VERSION 5.7 ;
  NOWIREEXTENSIONATPIN ON ;
  DIVIDERCHAR "/" ;
  BUSBITCHARS "[]" ;
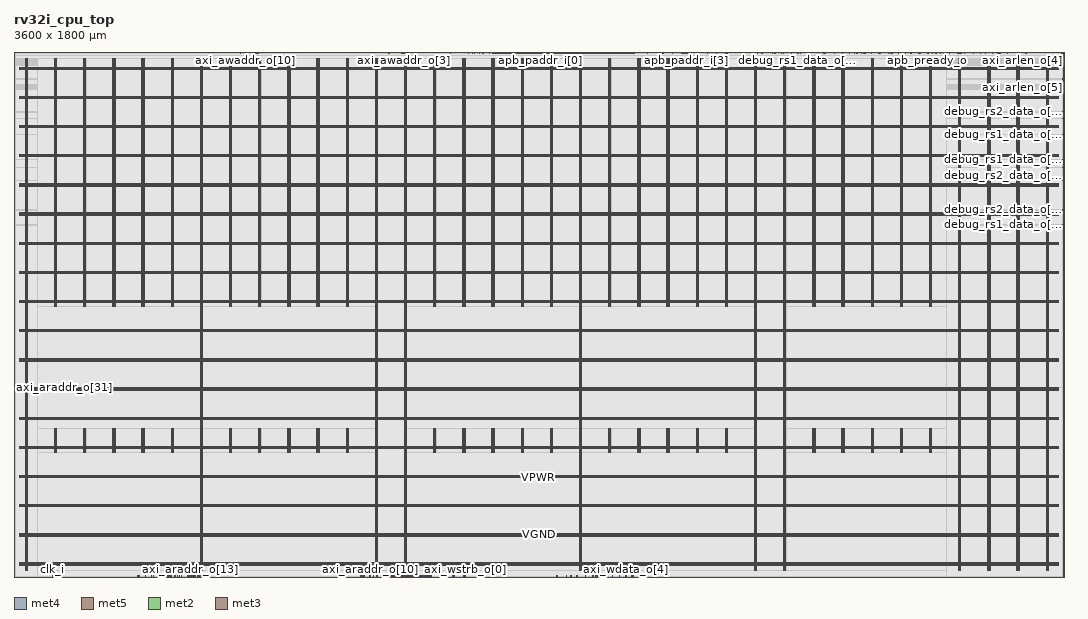
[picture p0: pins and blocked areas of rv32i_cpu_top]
MACRO rv32i_cpu_top
  CLASS BLOCK ;
  FOREIGN rv32i_cpu_top ;
  ORIGIN 0.000 0.000 ;
  SIZE 3600.000 BY 1800.000 ;
  PIN VGND
    DIRECTION INOUT ;
    USE GROUND ;
    PORT
      LAYER met4 ;
        RECT 43.490 21.520 46.590 1779.120 ;
    END
    PORT
      LAYER met4 ;
        RECT 143.490 427.280 146.590 510.220 ;
    END
    PORT
      LAYER met4 ;
        RECT 143.490 927.280 146.590 1779.120 ;
    END
    PORT
      LAYER met4 ;
        RECT 243.490 427.280 246.590 509.300 ;
    END
    PORT
      LAYER met4 ;
        RECT 243.490 927.280 246.590 1779.120 ;
    END
    PORT
      LAYER met4 ;
        RECT 343.490 427.280 346.590 509.300 ;
    END
    PORT
      LAYER met4 ;
        RECT 343.490 927.280 346.590 1779.120 ;
    END
    PORT
      LAYER met4 ;
        RECT 443.490 427.280 446.590 510.220 ;
    END
    PORT
      LAYER met4 ;
        RECT 443.490 927.280 446.590 1779.120 ;
    END
    PORT
      LAYER met4 ;
        RECT 543.490 427.280 546.590 510.220 ;
    END
    PORT
      LAYER met4 ;
        RECT 543.490 927.280 546.590 1779.120 ;
    END
    PORT
      LAYER met4 ;
        RECT 643.490 21.520 646.590 1779.120 ;
    END
    PORT
      LAYER met4 ;
        RECT 743.490 427.280 746.590 510.220 ;
    END
    PORT
      LAYER met4 ;
        RECT 743.490 927.280 746.590 1779.120 ;
    END
    PORT
      LAYER met4 ;
        RECT 843.490 428.200 846.590 509.300 ;
    END
    PORT
      LAYER met4 ;
        RECT 843.490 928.200 846.590 1779.120 ;
    END
    PORT
      LAYER met4 ;
        RECT 943.490 428.200 946.590 509.300 ;
    END
    PORT
      LAYER met4 ;
        RECT 943.490 928.200 946.590 1779.120 ;
    END
    PORT
      LAYER met4 ;
        RECT 1043.490 427.280 1046.590 510.220 ;
    END
    PORT
      LAYER met4 ;
        RECT 1043.490 927.280 1046.590 1779.120 ;
    END
    PORT
      LAYER met4 ;
        RECT 1143.490 427.280 1146.590 510.220 ;
    END
    PORT
      LAYER met4 ;
        RECT 1143.490 927.280 1146.590 1779.120 ;
    END
    PORT
      LAYER met4 ;
        RECT 1243.490 21.520 1246.590 1779.120 ;
    END
    PORT
      LAYER met4 ;
        RECT 1343.490 21.520 1346.590 1779.120 ;
    END
    PORT
      LAYER met4 ;
        RECT 1443.490 427.280 1446.590 509.300 ;
    END
    PORT
      LAYER met4 ;
        RECT 1443.490 927.280 1446.590 1779.120 ;
    END
    PORT
      LAYER met4 ;
        RECT 1543.490 428.200 1546.590 509.300 ;
    END
    PORT
      LAYER met4 ;
        RECT 1543.490 928.200 1546.590 1779.120 ;
    END
    PORT
      LAYER met4 ;
        RECT 1643.490 428.200 1646.590 509.300 ;
    END
    PORT
      LAYER met4 ;
        RECT 1643.490 928.200 1646.590 1779.120 ;
    END
    PORT
      LAYER met4 ;
        RECT 1743.490 427.280 1746.590 510.220 ;
    END
    PORT
      LAYER met4 ;
        RECT 1743.490 927.280 1746.590 1779.120 ;
    END
    PORT
      LAYER met4 ;
        RECT 1843.490 427.280 1846.590 510.220 ;
    END
    PORT
      LAYER met4 ;
        RECT 1843.490 927.280 1846.590 1779.120 ;
    END
    PORT
      LAYER met4 ;
        RECT 1943.490 21.520 1946.590 1779.120 ;
    END
    PORT
      LAYER met4 ;
        RECT 2043.490 427.280 2046.590 510.220 ;
    END
    PORT
      LAYER met4 ;
        RECT 2043.490 927.280 2046.590 1779.120 ;
    END
    PORT
      LAYER met4 ;
        RECT 2143.490 427.280 2146.590 509.300 ;
    END
    PORT
      LAYER met4 ;
        RECT 2143.490 927.280 2146.590 1779.120 ;
    END
    PORT
      LAYER met4 ;
        RECT 2243.490 428.200 2246.590 509.300 ;
    END
    PORT
      LAYER met4 ;
        RECT 2243.490 928.200 2246.590 1779.120 ;
    END
    PORT
      LAYER met4 ;
        RECT 2343.490 428.200 2346.590 510.220 ;
    END
    PORT
      LAYER met4 ;
        RECT 2343.490 928.200 2346.590 1779.120 ;
    END
    PORT
      LAYER met4 ;
        RECT 2443.490 427.280 2446.590 510.220 ;
    END
    PORT
      LAYER met4 ;
        RECT 2443.490 927.280 2446.590 1779.120 ;
    END
    PORT
      LAYER met4 ;
        RECT 2543.490 21.520 2546.590 1779.120 ;
    END
    PORT
      LAYER met4 ;
        RECT 2643.490 21.520 2646.590 1779.120 ;
    END
    PORT
      LAYER met4 ;
        RECT 2743.490 427.280 2746.590 510.220 ;
    END
    PORT
      LAYER met4 ;
        RECT 2743.490 927.280 2746.590 1779.120 ;
    END
    PORT
      LAYER met4 ;
        RECT 2843.490 427.280 2846.590 509.300 ;
    END
    PORT
      LAYER met4 ;
        RECT 2843.490 927.280 2846.590 1779.120 ;
    END
    PORT
      LAYER met4 ;
        RECT 2943.490 428.200 2946.590 509.300 ;
    END
    PORT
      LAYER met4 ;
        RECT 2943.490 928.200 2946.590 1779.120 ;
    END
    PORT
      LAYER met4 ;
        RECT 3043.490 428.200 3046.590 509.300 ;
    END
    PORT
      LAYER met4 ;
        RECT 3043.490 928.200 3046.590 1779.120 ;
    END
    PORT
      LAYER met4 ;
        RECT 3143.490 427.280 3146.590 510.220 ;
    END
    PORT
      LAYER met4 ;
        RECT 3143.490 927.280 3146.590 1779.120 ;
    END
    PORT
      LAYER met4 ;
        RECT 3243.490 21.520 3246.590 1779.120 ;
    END
    PORT
      LAYER met4 ;
        RECT 3343.490 21.520 3346.590 1779.120 ;
    END
    PORT
      LAYER met4 ;
        RECT 3443.490 21.520 3446.590 1779.120 ;
    END
    PORT
      LAYER met4 ;
        RECT 3543.490 21.520 3546.590 1779.120 ;
    END
    PORT
      LAYER met5 ;
        RECT 20.000 45.010 3579.960 48.110 ;
    END
    PORT
      LAYER met5 ;
        RECT 20.000 145.010 3579.960 148.110 ;
    END
    PORT
      LAYER met5 ;
        RECT 20.000 245.010 3579.960 248.110 ;
    END
    PORT
      LAYER met5 ;
        RECT 20.000 345.010 3579.960 348.110 ;
    END
    PORT
      LAYER met5 ;
        RECT 20.000 445.010 3579.960 448.110 ;
    END
    PORT
      LAYER met5 ;
        RECT 20.000 545.010 3579.960 548.110 ;
    END
    PORT
      LAYER met5 ;
        RECT 20.000 645.010 3579.960 648.110 ;
    END
    PORT
      LAYER met5 ;
        RECT 20.000 745.010 3579.960 748.110 ;
    END
    PORT
      LAYER met5 ;
        RECT 20.000 845.010 3579.960 848.110 ;
    END
    PORT
      LAYER met5 ;
        RECT 20.000 945.010 3579.960 948.110 ;
    END
    PORT
      LAYER met5 ;
        RECT 20.000 1045.010 3579.960 1048.110 ;
    END
    PORT
      LAYER met5 ;
        RECT 20.000 1145.010 3579.960 1148.110 ;
    END
    PORT
      LAYER met5 ;
        RECT 20.000 1245.010 3579.960 1248.110 ;
    END
    PORT
      LAYER met5 ;
        RECT 20.000 1345.010 3579.960 1348.110 ;
    END
    PORT
      LAYER met5 ;
        RECT 20.000 1445.010 3579.960 1448.110 ;
    END
    PORT
      LAYER met5 ;
        RECT 20.000 1545.010 3579.960 1548.110 ;
    END
    PORT
      LAYER met5 ;
        RECT 20.000 1645.010 3579.960 1648.110 ;
    END
    PORT
      LAYER met5 ;
        RECT 20.000 1745.010 3579.960 1748.110 ;
    END
  END VGND
  PIN VPWR
    DIRECTION INOUT ;
    USE POWER ;
    PORT
      LAYER met4 ;
        RECT 38.690 21.520 41.790 1779.120 ;
    END
    PORT
      LAYER met4 ;
        RECT 138.690 427.280 141.790 510.220 ;
    END
    PORT
      LAYER met4 ;
        RECT 138.690 927.280 141.790 1779.120 ;
    END
    PORT
      LAYER met4 ;
        RECT 238.690 428.200 241.790 509.300 ;
    END
    PORT
      LAYER met4 ;
        RECT 238.690 928.200 241.790 1779.120 ;
    END
    PORT
      LAYER met4 ;
        RECT 338.690 428.200 341.790 509.300 ;
    END
    PORT
      LAYER met4 ;
        RECT 338.690 928.200 341.790 1779.120 ;
    END
    PORT
      LAYER met4 ;
        RECT 438.690 427.280 441.790 510.220 ;
    END
    PORT
      LAYER met4 ;
        RECT 438.690 927.280 441.790 1779.120 ;
    END
    PORT
      LAYER met4 ;
        RECT 538.690 427.280 541.790 510.220 ;
    END
    PORT
      LAYER met4 ;
        RECT 538.690 927.280 541.790 1779.120 ;
    END
    PORT
      LAYER met4 ;
        RECT 638.690 21.520 641.790 1779.120 ;
    END
    PORT
      LAYER met4 ;
        RECT 738.690 427.280 741.790 510.220 ;
    END
    PORT
      LAYER met4 ;
        RECT 738.690 927.280 741.790 1779.120 ;
    END
    PORT
      LAYER met4 ;
        RECT 838.690 428.200 841.790 509.300 ;
    END
    PORT
      LAYER met4 ;
        RECT 838.690 928.200 841.790 1779.120 ;
    END
    PORT
      LAYER met4 ;
        RECT 938.690 428.200 941.790 509.300 ;
    END
    PORT
      LAYER met4 ;
        RECT 938.690 928.200 941.790 1779.120 ;
    END
    PORT
      LAYER met4 ;
        RECT 1038.690 427.280 1041.790 510.220 ;
    END
    PORT
      LAYER met4 ;
        RECT 1038.690 927.280 1041.790 1779.120 ;
    END
    PORT
      LAYER met4 ;
        RECT 1138.690 427.280 1141.790 510.220 ;
    END
    PORT
      LAYER met4 ;
        RECT 1138.690 927.280 1141.790 1779.120 ;
    END
    PORT
      LAYER met4 ;
        RECT 1238.690 21.520 1241.790 1779.120 ;
    END
    PORT
      LAYER met4 ;
        RECT 1338.690 21.520 1341.790 1779.120 ;
    END
    PORT
      LAYER met4 ;
        RECT 1438.690 427.280 1441.790 510.220 ;
    END
    PORT
      LAYER met4 ;
        RECT 1438.690 927.280 1441.790 1779.120 ;
    END
    PORT
      LAYER met4 ;
        RECT 1538.690 428.200 1541.790 509.300 ;
    END
    PORT
      LAYER met4 ;
        RECT 1538.690 928.200 1541.790 1779.120 ;
    END
    PORT
      LAYER met4 ;
        RECT 1638.690 428.200 1641.790 509.300 ;
    END
    PORT
      LAYER met4 ;
        RECT 1638.690 928.200 1641.790 1779.120 ;
    END
    PORT
      LAYER met4 ;
        RECT 1738.690 427.280 1741.790 510.220 ;
    END
    PORT
      LAYER met4 ;
        RECT 1738.690 927.280 1741.790 1779.120 ;
    END
    PORT
      LAYER met4 ;
        RECT 1838.690 427.280 1841.790 510.220 ;
    END
    PORT
      LAYER met4 ;
        RECT 1838.690 927.280 1841.790 1779.120 ;
    END
    PORT
      LAYER met4 ;
        RECT 1938.690 21.520 1941.790 1779.120 ;
    END
    PORT
      LAYER met4 ;
        RECT 2038.690 427.280 2041.790 510.220 ;
    END
    PORT
      LAYER met4 ;
        RECT 2038.690 927.280 2041.790 1779.120 ;
    END
    PORT
      LAYER met4 ;
        RECT 2138.690 427.280 2141.790 509.300 ;
    END
    PORT
      LAYER met4 ;
        RECT 2138.690 927.280 2141.790 1779.120 ;
    END
    PORT
      LAYER met4 ;
        RECT 2238.690 427.280 2241.790 509.300 ;
    END
    PORT
      LAYER met4 ;
        RECT 2238.690 927.280 2241.790 1779.120 ;
    END
    PORT
      LAYER met4 ;
        RECT 2338.690 427.280 2341.790 509.300 ;
    END
    PORT
      LAYER met4 ;
        RECT 2338.690 927.280 2341.790 1779.120 ;
    END
    PORT
      LAYER met4 ;
        RECT 2438.690 427.280 2441.790 510.220 ;
    END
    PORT
      LAYER met4 ;
        RECT 2438.690 927.280 2441.790 1779.120 ;
    END
    PORT
      LAYER met4 ;
        RECT 2538.690 21.520 2541.790 1779.120 ;
    END
    PORT
      LAYER met4 ;
        RECT 2638.690 21.520 2641.790 1779.120 ;
    END
    PORT
      LAYER met4 ;
        RECT 2738.690 427.280 2741.790 510.220 ;
    END
    PORT
      LAYER met4 ;
        RECT 2738.690 927.280 2741.790 1779.120 ;
    END
    PORT
      LAYER met4 ;
        RECT 2838.690 427.280 2841.790 510.220 ;
    END
    PORT
      LAYER met4 ;
        RECT 2838.690 927.280 2841.790 1779.120 ;
    END
    PORT
      LAYER met4 ;
        RECT 2938.690 428.200 2941.790 509.300 ;
    END
    PORT
      LAYER met4 ;
        RECT 2938.690 928.200 2941.790 1779.120 ;
    END
    PORT
      LAYER met4 ;
        RECT 3038.690 428.200 3041.790 509.300 ;
    END
    PORT
      LAYER met4 ;
        RECT 3038.690 928.200 3041.790 1779.120 ;
    END
    PORT
      LAYER met4 ;
        RECT 3138.690 427.280 3141.790 510.220 ;
    END
    PORT
      LAYER met4 ;
        RECT 3138.690 927.280 3141.790 1779.120 ;
    END
    PORT
      LAYER met4 ;
        RECT 3238.690 21.520 3241.790 1779.120 ;
    END
    PORT
      LAYER met4 ;
        RECT 3338.690 21.520 3341.790 1779.120 ;
    END
    PORT
      LAYER met4 ;
        RECT 3438.690 21.520 3441.790 1779.120 ;
    END
    PORT
      LAYER met4 ;
        RECT 3538.690 21.520 3541.790 1779.120 ;
    END
    PORT
      LAYER met5 ;
        RECT 20.000 40.210 3579.960 43.310 ;
    END
    PORT
      LAYER met5 ;
        RECT 20.000 140.210 3579.960 143.310 ;
    END
    PORT
      LAYER met5 ;
        RECT 20.000 240.210 3579.960 243.310 ;
    END
    PORT
      LAYER met5 ;
        RECT 20.000 340.210 3579.960 343.310 ;
    END
    PORT
      LAYER met5 ;
        RECT 20.000 440.210 3579.960 443.310 ;
    END
    PORT
      LAYER met5 ;
        RECT 20.000 540.210 3579.960 543.310 ;
    END
    PORT
      LAYER met5 ;
        RECT 20.000 640.210 3579.960 643.310 ;
    END
    PORT
      LAYER met5 ;
        RECT 20.000 740.210 3579.960 743.310 ;
    END
    PORT
      LAYER met5 ;
        RECT 20.000 840.210 3579.960 843.310 ;
    END
    PORT
      LAYER met5 ;
        RECT 20.000 940.210 3579.960 943.310 ;
    END
    PORT
      LAYER met5 ;
        RECT 20.000 1040.210 3579.960 1043.310 ;
    END
    PORT
      LAYER met5 ;
        RECT 20.000 1140.210 3579.960 1143.310 ;
    END
    PORT
      LAYER met5 ;
        RECT 20.000 1240.210 3579.960 1243.310 ;
    END
    PORT
      LAYER met5 ;
        RECT 20.000 1340.210 3579.960 1343.310 ;
    END
    PORT
      LAYER met5 ;
        RECT 20.000 1440.210 3579.960 1443.310 ;
    END
    PORT
      LAYER met5 ;
        RECT 20.000 1540.210 3579.960 1543.310 ;
    END
    PORT
      LAYER met5 ;
        RECT 20.000 1640.210 3579.960 1643.310 ;
    END
    PORT
      LAYER met5 ;
        RECT 20.000 1740.210 3579.960 1743.310 ;
    END
  END VPWR
  PIN apb_paddr_i[0]
    DIRECTION INPUT ;
    USE SIGNAL ;
    ANTENNAGATEAREA 0.647700 ;
    ANTENNADIFFAREA 0.434700 ;
    PORT
      LAYER met2 ;
        RECT 1806.510 1796.000 1806.790 1800.000 ;
    END
  END apb_paddr_i[0]
  PIN apb_paddr_i[10]
    DIRECTION INPUT ;
    USE SIGNAL ;
    ANTENNAGATEAREA 2.276700 ;
    ANTENNADIFFAREA 0.434700 ;
    PORT
      LAYER met2 ;
        RECT 1777.530 1796.000 1777.810 1800.000 ;
    END
  END apb_paddr_i[10]
  PIN apb_paddr_i[11]
    DIRECTION INPUT ;
    USE SIGNAL ;
    ANTENNAGATEAREA 0.929700 ;
    ANTENNADIFFAREA 0.434700 ;
    PORT
      LAYER met2 ;
        RECT 1774.310 1796.000 1774.590 1800.000 ;
    END
  END apb_paddr_i[11]
  PIN apb_paddr_i[1]
    DIRECTION INPUT ;
    USE SIGNAL ;
    ANTENNAGATEAREA 0.647700 ;
    ANTENNADIFFAREA 0.434700 ;
    PORT
      LAYER met2 ;
        RECT 1793.630 1796.000 1793.910 1800.000 ;
    END
  END apb_paddr_i[1]
  PIN apb_paddr_i[2]
    DIRECTION INPUT ;
    USE SIGNAL ;
    ANTENNAGATEAREA 0.647700 ;
    ANTENNADIFFAREA 0.434700 ;
    PORT
      LAYER met2 ;
        RECT 2308.830 1796.000 2309.110 1800.000 ;
    END
  END apb_paddr_i[2]
  PIN apb_paddr_i[3]
    DIRECTION INPUT ;
    USE SIGNAL ;
    ANTENNAGATEAREA 0.631200 ;
    ANTENNADIFFAREA 0.434700 ;
    PORT
      LAYER met2 ;
        RECT 2305.610 1796.000 2305.890 1800.000 ;
    END
  END apb_paddr_i[3]
  PIN apb_paddr_i[4]
    DIRECTION INPUT ;
    USE SIGNAL ;
    ANTENNAGATEAREA 0.929700 ;
    ANTENNADIFFAREA 0.434700 ;
    PORT
      LAYER met2 ;
        RECT 2302.390 1796.000 2302.670 1800.000 ;
    END
  END apb_paddr_i[4]
  PIN apb_paddr_i[5]
    DIRECTION INPUT ;
    USE SIGNAL ;
    ANTENNAGATEAREA 0.860700 ;
    ANTENNADIFFAREA 0.434700 ;
    PORT
      LAYER met2 ;
        RECT 2295.950 1796.000 2296.230 1800.000 ;
    END
  END apb_paddr_i[5]
  PIN apb_paddr_i[6]
    DIRECTION INPUT ;
    USE SIGNAL ;
    ANTENNAGATEAREA 0.860700 ;
    ANTENNADIFFAREA 0.434700 ;
    PORT
      LAYER met2 ;
        RECT 2299.170 1796.000 2299.450 1800.000 ;
    END
  END apb_paddr_i[6]
  PIN apb_paddr_i[7]
    DIRECTION INPUT ;
    USE SIGNAL ;
    ANTENNAGATEAREA 0.682200 ;
    ANTENNADIFFAREA 0.434700 ;
    PORT
      LAYER met2 ;
        RECT 2292.730 1796.000 2293.010 1800.000 ;
    END
  END apb_paddr_i[7]
  PIN apb_paddr_i[8]
    DIRECTION INPUT ;
    USE SIGNAL ;
    ANTENNAGATEAREA 1.177200 ;
    ANTENNADIFFAREA 0.434700 ;
    PORT
      LAYER met2 ;
        RECT 1780.750 1796.000 1781.030 1800.000 ;
    END
  END apb_paddr_i[8]
  PIN apb_paddr_i[9]
    DIRECTION INPUT ;
    USE SIGNAL ;
    ANTENNAGATEAREA 0.647700 ;
    ANTENNADIFFAREA 0.434700 ;
    PORT
      LAYER met2 ;
        RECT 1687.370 1796.000 1687.650 1800.000 ;
    END
  END apb_paddr_i[9]
  PIN apb_penable_i
    DIRECTION INPUT ;
    USE SIGNAL ;
    ANTENNAGATEAREA 0.560700 ;
    ANTENNADIFFAREA 0.434700 ;
    PORT
      LAYER met2 ;
        RECT 2128.510 1796.000 2128.790 1800.000 ;
    END
  END apb_penable_i
  PIN apb_prdata_o[0]
    DIRECTION OUTPUT ;
    USE SIGNAL ;
    ANTENNADIFFAREA 1.782000 ;
    PORT
      LAYER met2 ;
        RECT 1832.270 1796.000 1832.550 1800.000 ;
    END
  END apb_prdata_o[0]
  PIN apb_prdata_o[10]
    DIRECTION OUTPUT ;
    USE SIGNAL ;
    ANTENNADIFFAREA 1.336500 ;
    PORT
      LAYER met2 ;
        RECT 1809.730 1796.000 1810.010 1800.000 ;
    END
  END apb_prdata_o[10]
  PIN apb_prdata_o[11]
    DIRECTION OUTPUT ;
    USE SIGNAL ;
    ANTENNADIFFAREA 0.891000 ;
    PORT
      LAYER met2 ;
        RECT 1800.070 1796.000 1800.350 1800.000 ;
    END
  END apb_prdata_o[11]
  PIN apb_prdata_o[12]
    DIRECTION OUTPUT ;
    USE SIGNAL ;
    ANTENNADIFFAREA 1.782000 ;
    PORT
      LAYER met2 ;
        RECT 2080.210 1796.000 2080.490 1800.000 ;
    END
  END apb_prdata_o[12]
  PIN apb_prdata_o[13]
    DIRECTION OUTPUT ;
    USE SIGNAL ;
    ANTENNADIFFAREA 0.891000 ;
    PORT
      LAYER met2 ;
        RECT 2035.130 1796.000 2035.410 1800.000 ;
    END
  END apb_prdata_o[13]
  PIN apb_prdata_o[14]
    DIRECTION OUTPUT ;
    USE SIGNAL ;
    ANTENNADIFFAREA 2.673000 ;
    PORT
      LAYER met2 ;
        RECT 2070.550 1796.000 2070.830 1800.000 ;
    END
  END apb_prdata_o[14]
  PIN apb_prdata_o[15]
    DIRECTION OUTPUT ;
    USE SIGNAL ;
    ANTENNADIFFAREA 1.782000 ;
    PORT
      LAYER met2 ;
        RECT 1948.190 1796.000 1948.470 1800.000 ;
    END
  END apb_prdata_o[15]
  PIN apb_prdata_o[16]
    DIRECTION OUTPUT ;
    USE SIGNAL ;
    ANTENNADIFFAREA 0.891000 ;
    PORT
      LAYER met2 ;
        RECT 1941.750 1796.000 1942.030 1800.000 ;
    END
  END apb_prdata_o[16]
  PIN apb_prdata_o[17]
    DIRECTION OUTPUT ;
    USE SIGNAL ;
    ANTENNADIFFAREA 0.891000 ;
    PORT
      LAYER met2 ;
        RECT 1967.510 1796.000 1967.790 1800.000 ;
    END
  END apb_prdata_o[17]
  PIN apb_prdata_o[18]
    DIRECTION OUTPUT ;
    USE SIGNAL ;
    ANTENNADIFFAREA 1.336500 ;
    PORT
      LAYER met2 ;
        RECT 2006.150 1796.000 2006.430 1800.000 ;
    END
  END apb_prdata_o[18]
  PIN apb_prdata_o[19]
    DIRECTION OUTPUT ;
    USE SIGNAL ;
    ANTENNADIFFAREA 1.782000 ;
    PORT
      LAYER met2 ;
        RECT 1957.850 1796.000 1958.130 1800.000 ;
    END
  END apb_prdata_o[19]
  PIN apb_prdata_o[1]
    DIRECTION OUTPUT ;
    USE SIGNAL ;
    ANTENNADIFFAREA 2.673000 ;
    PORT
      LAYER met2 ;
        RECT 1767.870 1796.000 1768.150 1800.000 ;
    END
  END apb_prdata_o[1]
  PIN apb_prdata_o[20]
    DIRECTION OUTPUT ;
    USE SIGNAL ;
    ANTENNADIFFAREA 1.336500 ;
    PORT
      LAYER met2 ;
        RECT 2002.930 1796.000 2003.210 1800.000 ;
    END
  END apb_prdata_o[20]
  PIN apb_prdata_o[21]
    DIRECTION OUTPUT ;
    USE SIGNAL ;
    ANTENNADIFFAREA 2.673000 ;
    PORT
      LAYER met2 ;
        RECT 1925.650 1796.000 1925.930 1800.000 ;
    END
  END apb_prdata_o[21]
  PIN apb_prdata_o[22]
    DIRECTION OUTPUT ;
    USE SIGNAL ;
    ANTENNADIFFAREA 0.891000 ;
    PORT
      LAYER met2 ;
        RECT 1961.070 1796.000 1961.350 1800.000 ;
    END
  END apb_prdata_o[22]
  PIN apb_prdata_o[23]
    DIRECTION OUTPUT ;
    USE SIGNAL ;
    ANTENNADIFFAREA 1.782000 ;
    PORT
      LAYER met2 ;
        RECT 1964.290 1796.000 1964.570 1800.000 ;
    END
  END apb_prdata_o[23]
  PIN apb_prdata_o[24]
    DIRECTION OUTPUT ;
    USE SIGNAL ;
    ANTENNADIFFAREA 0.891000 ;
    PORT
      LAYER met2 ;
        RECT 2093.090 1796.000 2093.370 1800.000 ;
    END
  END apb_prdata_o[24]
  PIN apb_prdata_o[25]
    DIRECTION OUTPUT ;
    USE SIGNAL ;
    ANTENNADIFFAREA 0.891000 ;
    PORT
      LAYER met2 ;
        RECT 2112.410 1796.000 2112.690 1800.000 ;
    END
  END apb_prdata_o[25]
  PIN apb_prdata_o[26]
    DIRECTION OUTPUT ;
    USE SIGNAL ;
    ANTENNADIFFAREA 1.782000 ;
    PORT
      LAYER met2 ;
        RECT 2125.290 1796.000 2125.570 1800.000 ;
    END
  END apb_prdata_o[26]
  PIN apb_prdata_o[27]
    DIRECTION OUTPUT ;
    USE SIGNAL ;
    ANTENNADIFFAREA 0.891000 ;
    PORT
      LAYER met2 ;
        RECT 1883.790 1796.000 1884.070 1800.000 ;
    END
  END apb_prdata_o[27]
  PIN apb_prdata_o[28]
    DIRECTION OUTPUT ;
    USE SIGNAL ;
    ANTENNADIFFAREA 1.336500 ;
    PORT
      LAYER met2 ;
        RECT 1845.150 1796.000 1845.430 1800.000 ;
    END
  END apb_prdata_o[28]
  PIN apb_prdata_o[29]
    DIRECTION OUTPUT ;
    USE SIGNAL ;
    ANTENNADIFFAREA 1.782000 ;
    PORT
      LAYER met2 ;
        RECT 1877.350 1796.000 1877.630 1800.000 ;
    END
  END apb_prdata_o[29]
  PIN apb_prdata_o[2]
    DIRECTION OUTPUT ;
    USE SIGNAL ;
    ANTENNADIFFAREA 1.336500 ;
    PORT
      LAYER met2 ;
        RECT 1825.830 1796.000 1826.110 1800.000 ;
    END
  END apb_prdata_o[2]
  PIN apb_prdata_o[30]
    DIRECTION OUTPUT ;
    USE SIGNAL ;
    ANTENNADIFFAREA 1.782000 ;
    PORT
      LAYER met2 ;
        RECT 1870.910 1796.000 1871.190 1800.000 ;
    END
  END apb_prdata_o[30]
  PIN apb_prdata_o[31]
    DIRECTION OUTPUT ;
    USE SIGNAL ;
    ANTENNADIFFAREA 1.336500 ;
    PORT
      LAYER met2 ;
        RECT 1893.450 1796.000 1893.730 1800.000 ;
    END
  END apb_prdata_o[31]
  PIN apb_prdata_o[3]
    DIRECTION OUTPUT ;
    USE SIGNAL ;
    ANTENNADIFFAREA 1.782000 ;
    PORT
      LAYER met2 ;
        RECT 2044.790 1796.000 2045.070 1800.000 ;
    END
  END apb_prdata_o[3]
  PIN apb_prdata_o[4]
    DIRECTION OUTPUT ;
    USE SIGNAL ;
    ANTENNADIFFAREA 2.673000 ;
    PORT
      LAYER met2 ;
        RECT 2048.010 1796.000 2048.290 1800.000 ;
    END
  END apb_prdata_o[4]
  PIN apb_prdata_o[5]
    DIRECTION OUTPUT ;
    USE SIGNAL ;
    ANTENNADIFFAREA 1.782000 ;
    PORT
      LAYER met2 ;
        RECT 2028.690 1796.000 2028.970 1800.000 ;
    END
  END apb_prdata_o[5]
  PIN apb_prdata_o[6]
    DIRECTION OUTPUT ;
    USE SIGNAL ;
    ANTENNADIFFAREA 1.782000 ;
    PORT
      LAYER met2 ;
        RECT 2031.910 1796.000 2032.190 1800.000 ;
    END
  END apb_prdata_o[6]
  PIN apb_prdata_o[7]
    DIRECTION OUTPUT ;
    USE SIGNAL ;
    ANTENNADIFFAREA 1.336500 ;
    PORT
      LAYER met2 ;
        RECT 2083.430 1796.000 2083.710 1800.000 ;
    END
  END apb_prdata_o[7]
  PIN apb_prdata_o[8]
    DIRECTION OUTPUT ;
    USE SIGNAL ;
    ANTENNADIFFAREA 0.891000 ;
    PORT
      LAYER met2 ;
        RECT 1909.550 1796.000 1909.830 1800.000 ;
    END
  END apb_prdata_o[8]
  PIN apb_prdata_o[9]
    DIRECTION OUTPUT ;
    USE SIGNAL ;
    ANTENNADIFFAREA 0.891000 ;
    PORT
      LAYER met2 ;
        RECT 1993.270 1796.000 1993.550 1800.000 ;
    END
  END apb_prdata_o[9]
  PIN apb_pready_o
    DIRECTION OUTPUT ;
    USE SIGNAL ;
    PORT
      LAYER met2 ;
        RECT 3133.150 1796.000 3133.430 1800.000 ;
    END
  END apb_pready_o
  PIN apb_psel_i
    DIRECTION INPUT ;
    USE SIGNAL ;
    ANTENNAGATEAREA 0.682200 ;
    ANTENNADIFFAREA 0.434700 ;
    PORT
      LAYER met2 ;
        RECT 2038.350 1796.000 2038.630 1800.000 ;
    END
  END apb_psel_i
  PIN apb_pslverr_o
    DIRECTION OUTPUT ;
    USE SIGNAL ;
    ANTENNADIFFAREA 0.891000 ;
    PORT
      LAYER met2 ;
        RECT 2051.230 1796.000 2051.510 1800.000 ;
    END
  END apb_pslverr_o
  PIN apb_pwdata_i[0]
    DIRECTION INPUT ;
    USE SIGNAL ;
    ANTENNAGATEAREA 0.560700 ;
    ANTENNADIFFAREA 0.434700 ;
    PORT
      LAYER met2 ;
        RECT 2067.330 1796.000 2067.610 1800.000 ;
    END
  END apb_pwdata_i[0]
  PIN apb_pwdata_i[10]
    DIRECTION INPUT ;
    USE SIGNAL ;
    ANTENNAGATEAREA 0.560700 ;
    ANTENNADIFFAREA 0.434700 ;
    PORT
      LAYER met2 ;
        RECT 1787.190 1796.000 1787.470 1800.000 ;
    END
  END apb_pwdata_i[10]
  PIN apb_pwdata_i[11]
    DIRECTION INPUT ;
    USE SIGNAL ;
    ANTENNAGATEAREA 0.560700 ;
    ANTENNADIFFAREA 0.434700 ;
    PORT
      LAYER met2 ;
        RECT 2076.990 1796.000 2077.270 1800.000 ;
    END
  END apb_pwdata_i[11]
  PIN apb_pwdata_i[12]
    DIRECTION INPUT ;
    USE SIGNAL ;
    ANTENNAGATEAREA 0.995400 ;
    ANTENNADIFFAREA 0.869400 ;
    PORT
      LAYER met2 ;
        RECT 2025.470 1796.000 2025.750 1800.000 ;
    END
  END apb_pwdata_i[12]
  PIN apb_pwdata_i[13]
    DIRECTION INPUT ;
    USE SIGNAL ;
    ANTENNAGATEAREA 0.560700 ;
    ANTENNADIFFAREA 0.434700 ;
    PORT
      LAYER met2 ;
        RECT 2019.030 1796.000 2019.310 1800.000 ;
    END
  END apb_pwdata_i[13]
  PIN apb_pwdata_i[14]
    DIRECTION INPUT ;
    USE SIGNAL ;
    ANTENNAGATEAREA 0.560700 ;
    ANTENNADIFFAREA 0.434700 ;
    PORT
      LAYER met2 ;
        RECT 2054.450 1796.000 2054.730 1800.000 ;
    END
  END apb_pwdata_i[14]
  PIN apb_pwdata_i[15]
    DIRECTION INPUT ;
    USE SIGNAL ;
    ANTENNAGATEAREA 0.560700 ;
    ANTENNADIFFAREA 0.434700 ;
    PORT
      LAYER met2 ;
        RECT 2022.250 1796.000 2022.530 1800.000 ;
    END
  END apb_pwdata_i[15]
  PIN apb_pwdata_i[16]
    DIRECTION INPUT ;
    USE SIGNAL ;
    ANTENNAGATEAREA 0.560700 ;
    ANTENNADIFFAREA 0.434700 ;
    PORT
      LAYER met2 ;
        RECT 1703.470 1796.000 1703.750 1800.000 ;
    END
  END apb_pwdata_i[16]
  PIN apb_pwdata_i[17]
    DIRECTION INPUT ;
    USE SIGNAL ;
    ANTENNAGATEAREA 0.560700 ;
    ANTENNADIFFAREA 0.434700 ;
    PORT
      LAYER met2 ;
        RECT 1990.050 1796.000 1990.330 1800.000 ;
    END
  END apb_pwdata_i[17]
  PIN apb_pwdata_i[18]
    DIRECTION INPUT ;
    USE SIGNAL ;
    ANTENNAGATEAREA 0.995400 ;
    ANTENNADIFFAREA 0.869400 ;
    PORT
      LAYER met2 ;
        RECT 2060.890 1796.000 2061.170 1800.000 ;
    END
  END apb_pwdata_i[18]
  PIN apb_pwdata_i[19]
    DIRECTION INPUT ;
    USE SIGNAL ;
    ANTENNAGATEAREA 0.560700 ;
    ANTENNADIFFAREA 0.434700 ;
    PORT
      LAYER met2 ;
        RECT 1697.030 1796.000 1697.310 1800.000 ;
    END
  END apb_pwdata_i[19]
  PIN apb_pwdata_i[1]
    DIRECTION INPUT ;
    USE SIGNAL ;
    ANTENNAGATEAREA 0.560700 ;
    ANTENNADIFFAREA 0.434700 ;
    PORT
      LAYER met2 ;
        RECT 1754.990 1796.000 1755.270 1800.000 ;
    END
  END apb_pwdata_i[1]
  PIN apb_pwdata_i[20]
    DIRECTION INPUT ;
    USE SIGNAL ;
    ANTENNAGATEAREA 0.560700 ;
    ANTENNADIFFAREA 0.434700 ;
    PORT
      LAYER met2 ;
        RECT 1999.710 1796.000 1999.990 1800.000 ;
    END
  END apb_pwdata_i[20]
  PIN apb_pwdata_i[21]
    DIRECTION INPUT ;
    USE SIGNAL ;
    ANTENNAGATEAREA 0.560700 ;
    ANTENNADIFFAREA 0.434700 ;
    PORT
      LAYER met2 ;
        RECT 1722.790 1796.000 1723.070 1800.000 ;
    END
  END apb_pwdata_i[21]
  PIN apb_pwdata_i[22]
    DIRECTION INPUT ;
    USE SIGNAL ;
    ANTENNAGATEAREA 0.560700 ;
    ANTENNADIFFAREA 0.434700 ;
    PORT
      LAYER met2 ;
        RECT 2057.670 1796.000 2057.950 1800.000 ;
    END
  END apb_pwdata_i[22]
  PIN apb_pwdata_i[23]
    DIRECTION INPUT ;
    USE SIGNAL ;
    ANTENNAGATEAREA 0.560700 ;
    ANTENNADIFFAREA 0.434700 ;
    PORT
      LAYER met2 ;
        RECT 2012.590 1796.000 2012.870 1800.000 ;
    END
  END apb_pwdata_i[23]
  PIN apb_pwdata_i[24]
    DIRECTION INPUT ;
    USE SIGNAL ;
    ANTENNAGATEAREA 0.560700 ;
    ANTENNADIFFAREA 0.434700 ;
    PORT
      LAYER met2 ;
        RECT 2073.770 1796.000 2074.050 1800.000 ;
    END
  END apb_pwdata_i[24]
  PIN apb_pwdata_i[25]
    DIRECTION INPUT ;
    USE SIGNAL ;
    ANTENNAGATEAREA 0.560700 ;
    ANTENNADIFFAREA 0.434700 ;
    PORT
      LAYER met2 ;
        RECT 1983.610 1796.000 1983.890 1800.000 ;
    END
  END apb_pwdata_i[25]
  PIN apb_pwdata_i[26]
    DIRECTION INPUT ;
    USE SIGNAL ;
    ANTENNAGATEAREA 0.560700 ;
    ANTENNADIFFAREA 0.434700 ;
    PORT
      LAYER met2 ;
        RECT 2064.110 1796.000 2064.390 1800.000 ;
    END
  END apb_pwdata_i[26]
  PIN apb_pwdata_i[27]
    DIRECTION INPUT ;
    USE SIGNAL ;
    ANTENNAGATEAREA 0.560700 ;
    ANTENNADIFFAREA 0.434700 ;
    PORT
      LAYER met2 ;
        RECT 1732.450 1796.000 1732.730 1800.000 ;
    END
  END apb_pwdata_i[27]
  PIN apb_pwdata_i[28]
    DIRECTION INPUT ;
    USE SIGNAL ;
    ANTENNAGATEAREA 0.560700 ;
    ANTENNADIFFAREA 0.434700 ;
    PORT
      LAYER met2 ;
        RECT 1735.670 1796.000 1735.950 1800.000 ;
    END
  END apb_pwdata_i[28]
  PIN apb_pwdata_i[29]
    DIRECTION INPUT ;
    USE SIGNAL ;
    ANTENNAGATEAREA 0.560700 ;
    ANTENNADIFFAREA 0.434700 ;
    PORT
      LAYER met2 ;
        RECT 1726.010 1796.000 1726.290 1800.000 ;
    END
  END apb_pwdata_i[29]
  PIN apb_pwdata_i[2]
    DIRECTION INPUT ;
    USE SIGNAL ;
    ANTENNAGATEAREA 0.560700 ;
    ANTENNADIFFAREA 0.434700 ;
    PORT
      LAYER met2 ;
        RECT 2009.370 1796.000 2009.650 1800.000 ;
    END
  END apb_pwdata_i[2]
  PIN apb_pwdata_i[30]
    DIRECTION INPUT ;
    USE SIGNAL ;
    ANTENNAGATEAREA 0.560700 ;
    ANTENNADIFFAREA 0.434700 ;
    PORT
      LAYER met2 ;
        RECT 1771.090 1796.000 1771.370 1800.000 ;
    END
  END apb_pwdata_i[30]
  PIN apb_pwdata_i[31]
    DIRECTION INPUT ;
    USE SIGNAL ;
    ANTENNAGATEAREA 0.560700 ;
    ANTENNADIFFAREA 0.434700 ;
    PORT
      LAYER met2 ;
        RECT 1761.430 1796.000 1761.710 1800.000 ;
    END
  END apb_pwdata_i[31]
  PIN apb_pwdata_i[3]
    DIRECTION INPUT ;
    USE SIGNAL ;
    ANTENNAGATEAREA 0.560700 ;
    ANTENNADIFFAREA 0.434700 ;
    PORT
      LAYER met2 ;
        RECT 1751.770 1796.000 1752.050 1800.000 ;
    END
  END apb_pwdata_i[3]
  PIN apb_pwdata_i[4]
    DIRECTION INPUT ;
    USE SIGNAL ;
    ANTENNAGATEAREA 0.560700 ;
    ANTENNADIFFAREA 0.434700 ;
    PORT
      LAYER met2 ;
        RECT 1758.210 1796.000 1758.490 1800.000 ;
    END
  END apb_pwdata_i[4]
  PIN apb_pwdata_i[5]
    DIRECTION INPUT ;
    USE SIGNAL ;
    ANTENNAGATEAREA 0.560700 ;
    ANTENNADIFFAREA 0.434700 ;
    PORT
      LAYER met2 ;
        RECT 1745.330 1796.000 1745.610 1800.000 ;
    END
  END apb_pwdata_i[5]
  PIN apb_pwdata_i[6]
    DIRECTION INPUT ;
    USE SIGNAL ;
    ANTENNAGATEAREA 0.560700 ;
    ANTENNADIFFAREA 0.434700 ;
    PORT
      LAYER met2 ;
        RECT 1783.970 1796.000 1784.250 1800.000 ;
    END
  END apb_pwdata_i[6]
  PIN apb_pwdata_i[7]
    DIRECTION INPUT ;
    USE SIGNAL ;
    ANTENNAGATEAREA 0.560700 ;
    ANTENNADIFFAREA 0.434700 ;
    PORT
      LAYER met2 ;
        RECT 1764.650 1796.000 1764.930 1800.000 ;
    END
  END apb_pwdata_i[7]
  PIN apb_pwdata_i[8]
    DIRECTION INPUT ;
    USE SIGNAL ;
    ANTENNAGATEAREA 0.560700 ;
    ANTENNADIFFAREA 0.434700 ;
    PORT
      LAYER met2 ;
        RECT 1829.050 1796.000 1829.330 1800.000 ;
    END
  END apb_pwdata_i[8]
  PIN apb_pwdata_i[9]
    DIRECTION INPUT ;
    USE SIGNAL ;
    ANTENNAGATEAREA 0.560700 ;
    ANTENNADIFFAREA 0.434700 ;
    PORT
      LAYER met2 ;
        RECT 1986.830 1796.000 1987.110 1800.000 ;
    END
  END apb_pwdata_i[9]
  PIN apb_pwrite_i
    DIRECTION INPUT ;
    USE SIGNAL ;
    ANTENNAGATEAREA 0.682200 ;
    ANTENNADIFFAREA 0.434700 ;
    PORT
      LAYER met2 ;
        RECT 2041.570 1796.000 2041.850 1800.000 ;
    END
  END apb_pwrite_i
  PIN axi_araddr_o[0]
    DIRECTION OUTPUT ;
    USE SIGNAL ;
    PORT
      LAYER met3 ;
        RECT 3596.000 1778.240 3600.000 1778.840 ;
    END
  END axi_araddr_o[0]
  PIN axi_araddr_o[10]
    DIRECTION OUTPUT ;
    USE SIGNAL ;
    ANTENNADIFFAREA 0.891000 ;
    PORT
      LAYER met2 ;
        RECT 1220.470 0.000 1220.750 4.000 ;
    END
  END axi_araddr_o[10]
  PIN axi_araddr_o[11]
    DIRECTION OUTPUT ;
    USE SIGNAL ;
    ANTENNADIFFAREA 0.891000 ;
    PORT
      LAYER met2 ;
        RECT 1246.230 0.000 1246.510 4.000 ;
    END
  END axi_araddr_o[11]
  PIN axi_araddr_o[12]
    DIRECTION OUTPUT ;
    USE SIGNAL ;
    ANTENNADIFFAREA 0.891000 ;
    PORT
      LAYER met2 ;
        RECT 595.790 0.000 596.070 4.000 ;
    END
  END axi_araddr_o[12]
  PIN axi_araddr_o[13]
    DIRECTION OUTPUT ;
    USE SIGNAL ;
    ANTENNADIFFAREA 0.891000 ;
    PORT
      LAYER met2 ;
        RECT 605.450 0.000 605.730 4.000 ;
    END
  END axi_araddr_o[13]
  PIN axi_araddr_o[14]
    DIRECTION OUTPUT ;
    USE SIGNAL ;
    ANTENNADIFFAREA 0.891000 ;
    PORT
      LAYER met2 ;
        RECT 618.330 0.000 618.610 4.000 ;
    END
  END axi_araddr_o[14]
  PIN axi_araddr_o[15]
    DIRECTION OUTPUT ;
    USE SIGNAL ;
    ANTENNADIFFAREA 0.891000 ;
    PORT
      LAYER met2 ;
        RECT 608.670 0.000 608.950 4.000 ;
    END
  END axi_araddr_o[15]
  PIN axi_araddr_o[16]
    DIRECTION OUTPUT ;
    USE SIGNAL ;
    ANTENNADIFFAREA 0.891000 ;
    PORT
      LAYER met2 ;
        RECT 599.010 0.000 599.290 4.000 ;
    END
  END axi_araddr_o[16]
  PIN axi_araddr_o[17]
    DIRECTION OUTPUT ;
    USE SIGNAL ;
    ANTENNADIFFAREA 0.891000 ;
    PORT
      LAYER met2 ;
        RECT 602.230 0.000 602.510 4.000 ;
    END
  END axi_araddr_o[17]
  PIN axi_araddr_o[18]
    DIRECTION OUTPUT ;
    USE SIGNAL ;
    ANTENNADIFFAREA 0.891000 ;
    PORT
      LAYER met2 ;
        RECT 615.110 0.000 615.390 4.000 ;
    END
  END axi_araddr_o[18]
  PIN axi_araddr_o[19]
    DIRECTION OUTPUT ;
    USE SIGNAL ;
    ANTENNADIFFAREA 0.891000 ;
    PORT
      LAYER met2 ;
        RECT 611.890 0.000 612.170 4.000 ;
    END
  END axi_araddr_o[19]
  PIN axi_araddr_o[1]
    DIRECTION OUTPUT ;
    USE SIGNAL ;
    PORT
      LAYER met2 ;
        RECT 2408.650 1796.000 2408.930 1800.000 ;
    END
  END axi_araddr_o[1]
  PIN axi_araddr_o[20]
    DIRECTION OUTPUT ;
    USE SIGNAL ;
    ANTENNADIFFAREA 0.891000 ;
    PORT
      LAYER met2 ;
        RECT 631.210 0.000 631.490 4.000 ;
    END
  END axi_araddr_o[20]
  PIN axi_araddr_o[21]
    DIRECTION OUTPUT ;
    USE SIGNAL ;
    ANTENNADIFFAREA 0.891000 ;
    PORT
      LAYER met2 ;
        RECT 650.530 0.000 650.810 4.000 ;
    END
  END axi_araddr_o[21]
  PIN axi_araddr_o[22]
    DIRECTION OUTPUT ;
    USE SIGNAL ;
    ANTENNADIFFAREA 0.891000 ;
    PORT
      LAYER met2 ;
        RECT 653.750 0.000 654.030 4.000 ;
    END
  END axi_araddr_o[22]
  PIN axi_araddr_o[23]
    DIRECTION OUTPUT ;
    USE SIGNAL ;
    ANTENNADIFFAREA 0.891000 ;
    PORT
      LAYER met2 ;
        RECT 644.090 0.000 644.370 4.000 ;
    END
  END axi_araddr_o[23]
  PIN axi_araddr_o[24]
    DIRECTION OUTPUT ;
    USE SIGNAL ;
    ANTENNADIFFAREA 0.891000 ;
    PORT
      LAYER met2 ;
        RECT 660.190 0.000 660.470 4.000 ;
    END
  END axi_araddr_o[24]
  PIN axi_araddr_o[25]
    DIRECTION OUTPUT ;
    USE SIGNAL ;
    ANTENNADIFFAREA 0.891000 ;
    PORT
      LAYER met2 ;
        RECT 627.990 0.000 628.270 4.000 ;
    END
  END axi_araddr_o[25]
  PIN axi_araddr_o[26]
    DIRECTION OUTPUT ;
    USE SIGNAL ;
    ANTENNADIFFAREA 0.891000 ;
    PORT
      LAYER met2 ;
        RECT 634.430 0.000 634.710 4.000 ;
    END
  END axi_araddr_o[26]
  PIN axi_araddr_o[27]
    DIRECTION OUTPUT ;
    USE SIGNAL ;
    ANTENNADIFFAREA 0.891000 ;
    PORT
      LAYER met2 ;
        RECT 656.970 0.000 657.250 4.000 ;
    END
  END axi_araddr_o[27]
  PIN axi_araddr_o[28]
    DIRECTION OUTPUT ;
    USE SIGNAL ;
    ANTENNADIFFAREA 0.891000 ;
    PORT
      LAYER met2 ;
        RECT 621.550 0.000 621.830 4.000 ;
    END
  END axi_araddr_o[28]
  PIN axi_araddr_o[29]
    DIRECTION OUTPUT ;
    USE SIGNAL ;
    ANTENNADIFFAREA 0.891000 ;
    PORT
      LAYER met2 ;
        RECT 637.650 0.000 637.930 4.000 ;
    END
  END axi_araddr_o[29]
  PIN axi_araddr_o[2]
    DIRECTION OUTPUT ;
    USE SIGNAL ;
    ANTENNADIFFAREA 0.891000 ;
    PORT
      LAYER met2 ;
        RECT 1510.270 0.000 1510.550 4.000 ;
    END
  END axi_araddr_o[2]
  PIN axi_araddr_o[30]
    DIRECTION OUTPUT ;
    USE SIGNAL ;
    ANTENNADIFFAREA 0.891000 ;
    PORT
      LAYER met2 ;
        RECT 640.870 0.000 641.150 4.000 ;
    END
  END axi_araddr_o[30]
  PIN axi_araddr_o[31]
    DIRECTION OUTPUT ;
    USE SIGNAL ;
    ANTENNADIFFAREA 0.891000 ;
    PORT
      LAYER met3 ;
        RECT 0.000 649.440 4.000 650.040 ;
    END
  END axi_araddr_o[31]
  PIN axi_araddr_o[3]
    DIRECTION OUTPUT ;
    USE SIGNAL ;
    ANTENNADIFFAREA 0.891000 ;
    PORT
      LAYER met2 ;
        RECT 1507.050 0.000 1507.330 4.000 ;
    END
  END axi_araddr_o[3]
  PIN axi_araddr_o[4]
    DIRECTION OUTPUT ;
    USE SIGNAL ;
    ANTENNADIFFAREA 0.891000 ;
    PORT
      LAYER met2 ;
        RECT 1194.710 0.000 1194.990 4.000 ;
    END
  END axi_araddr_o[4]
  PIN axi_araddr_o[5]
    DIRECTION OUTPUT ;
    USE SIGNAL ;
    ANTENNADIFFAREA 0.891000 ;
    PORT
      LAYER met2 ;
        RECT 1191.490 0.000 1191.770 4.000 ;
    END
  END axi_araddr_o[5]
  PIN axi_araddr_o[6]
    DIRECTION OUTPUT ;
    USE SIGNAL ;
    ANTENNADIFFAREA 0.891000 ;
    PORT
      LAYER met2 ;
        RECT 1188.270 0.000 1188.550 4.000 ;
    END
  END axi_araddr_o[6]
  PIN axi_araddr_o[7]
    DIRECTION OUTPUT ;
    USE SIGNAL ;
    ANTENNADIFFAREA 0.891000 ;
    PORT
      LAYER met2 ;
        RECT 1197.930 0.000 1198.210 4.000 ;
    END
  END axi_araddr_o[7]
  PIN axi_araddr_o[8]
    DIRECTION OUTPUT ;
    USE SIGNAL ;
    ANTENNADIFFAREA 0.891000 ;
    PORT
      LAYER met2 ;
        RECT 1201.150 0.000 1201.430 4.000 ;
    END
  END axi_araddr_o[8]
  PIN axi_araddr_o[9]
    DIRECTION OUTPUT ;
    USE SIGNAL ;
    ANTENNADIFFAREA 0.891000 ;
    PORT
      LAYER met2 ;
        RECT 1243.010 0.000 1243.290 4.000 ;
    END
  END axi_araddr_o[9]
  PIN axi_arburst_o[0]
    DIRECTION OUTPUT ;
    USE SIGNAL ;
    ANTENNADIFFAREA 0.891000 ;
    PORT
      LAYER met2 ;
        RECT 1223.690 0.000 1223.970 4.000 ;
    END
  END axi_arburst_o[0]
  PIN axi_arburst_o[1]
    DIRECTION OUTPUT ;
    USE SIGNAL ;
    PORT
      LAYER met2 ;
        RECT 2376.450 1796.000 2376.730 1800.000 ;
    END
  END axi_arburst_o[1]
  PIN axi_arlen_o[0]
    DIRECTION OUTPUT ;
    USE SIGNAL ;
    ANTENNADIFFAREA 0.891000 ;
    PORT
      LAYER met2 ;
        RECT 1426.550 0.000 1426.830 4.000 ;
    END
  END axi_arlen_o[0]
  PIN axi_arlen_o[1]
    DIRECTION OUTPUT ;
    USE SIGNAL ;
    ANTENNADIFFAREA 0.891000 ;
    PORT
      LAYER met2 ;
        RECT 1423.330 0.000 1423.610 4.000 ;
    END
  END axi_arlen_o[1]
  PIN axi_arlen_o[2]
    DIRECTION OUTPUT ;
    USE SIGNAL ;
    PORT
      LAYER met2 ;
        RECT 2566.430 1796.000 2566.710 1800.000 ;
    END
  END axi_arlen_o[2]
  PIN axi_arlen_o[3]
    DIRECTION OUTPUT ;
    USE SIGNAL ;
    PORT
      LAYER met3 ;
        RECT 3596.000 1774.840 3600.000 1775.440 ;
    END
  END axi_arlen_o[3]
  PIN axi_arlen_o[4]
    DIRECTION OUTPUT ;
    USE SIGNAL ;
    PORT
      LAYER met2 ;
        RECT 3468.030 1796.000 3468.310 1800.000 ;
    END
  END axi_arlen_o[4]
  PIN axi_arlen_o[5]
    DIRECTION OUTPUT ;
    USE SIGNAL ;
    PORT
      LAYER met3 ;
        RECT 3596.000 1679.640 3600.000 1680.240 ;
    END
  END axi_arlen_o[5]
  PIN axi_arlen_o[6]
    DIRECTION OUTPUT ;
    USE SIGNAL ;
    PORT
      LAYER met2 ;
        RECT 3162.130 1796.000 3162.410 1800.000 ;
    END
  END axi_arlen_o[6]
  PIN axi_arlen_o[7]
    DIRECTION OUTPUT ;
    USE SIGNAL ;
    PORT
      LAYER met2 ;
        RECT 3329.570 1796.000 3329.850 1800.000 ;
    END
  END axi_arlen_o[7]
  PIN axi_arready_i
    DIRECTION INPUT ;
    USE SIGNAL ;
    ANTENNAGATEAREA 0.560700 ;
    ANTENNADIFFAREA 0.434700 ;
    PORT
      LAYER met2 ;
        RECT 1294.530 0.000 1294.810 4.000 ;
    END
  END axi_arready_i
  PIN axi_arsize_o[0]
    DIRECTION OUTPUT ;
    USE SIGNAL ;
    PORT
      LAYER met2 ;
        RECT 3136.370 1796.000 3136.650 1800.000 ;
    END
  END axi_arsize_o[0]
  PIN axi_arsize_o[1]
    DIRECTION OUTPUT ;
    USE SIGNAL ;
    ANTENNADIFFAREA 0.891000 ;
    PORT
      LAYER met2 ;
        RECT 1233.350 0.000 1233.630 4.000 ;
    END
  END axi_arsize_o[1]
  PIN axi_arsize_o[2]
    DIRECTION OUTPUT ;
    USE SIGNAL ;
    PORT
      LAYER met2 ;
        RECT 2888.430 1796.000 2888.710 1800.000 ;
    END
  END axi_arsize_o[2]
  PIN axi_arvalid_o
    DIRECTION OUTPUT ;
    USE SIGNAL ;
    ANTENNADIFFAREA 0.891000 ;
    PORT
      LAYER met2 ;
        RECT 1278.430 0.000 1278.710 4.000 ;
    END
  END axi_arvalid_o
  PIN axi_awaddr_o[0]
    DIRECTION OUTPUT ;
    USE SIGNAL ;
    PORT
      LAYER met2 ;
        RECT 3187.890 1796.000 3188.170 1800.000 ;
    END
  END axi_awaddr_o[0]
  PIN axi_awaddr_o[10]
    DIRECTION OUTPUT ;
    USE SIGNAL ;
    ANTENNADIFFAREA 0.891000 ;
    PORT
      LAYER met2 ;
        RECT 792.210 1796.000 792.490 1800.000 ;
    END
  END axi_awaddr_o[10]
  PIN axi_awaddr_o[11]
    DIRECTION OUTPUT ;
    USE SIGNAL ;
    ANTENNADIFFAREA 0.891000 ;
    PORT
      LAYER met2 ;
        RECT 776.110 1796.000 776.390 1800.000 ;
    END
  END axi_awaddr_o[11]
  PIN axi_awaddr_o[12]
    DIRECTION OUTPUT ;
    USE SIGNAL ;
    ANTENNADIFFAREA 0.891000 ;
    PORT
      LAYER met2 ;
        RECT 560.370 0.000 560.650 4.000 ;
    END
  END axi_awaddr_o[12]
  PIN axi_awaddr_o[13]
    DIRECTION OUTPUT ;
    USE SIGNAL ;
    ANTENNADIFFAREA 0.891000 ;
    PORT
      LAYER met2 ;
        RECT 550.710 0.000 550.990 4.000 ;
    END
  END axi_awaddr_o[13]
  PIN axi_awaddr_o[14]
    DIRECTION OUTPUT ;
    USE SIGNAL ;
    ANTENNADIFFAREA 0.891000 ;
    PORT
      LAYER met2 ;
        RECT 524.950 0.000 525.230 4.000 ;
    END
  END axi_awaddr_o[14]
  PIN axi_awaddr_o[15]
    DIRECTION OUTPUT ;
    USE SIGNAL ;
    ANTENNADIFFAREA 0.891000 ;
    PORT
      LAYER met2 ;
        RECT 541.050 0.000 541.330 4.000 ;
    END
  END axi_awaddr_o[15]
  PIN axi_awaddr_o[16]
    DIRECTION OUTPUT ;
    USE SIGNAL ;
    ANTENNADIFFAREA 0.891000 ;
    PORT
      LAYER met2 ;
        RECT 531.390 0.000 531.670 4.000 ;
    END
  END axi_awaddr_o[16]
  PIN axi_awaddr_o[17]
    DIRECTION OUTPUT ;
    USE SIGNAL ;
    ANTENNADIFFAREA 0.891000 ;
    PORT
      LAYER met2 ;
        RECT 528.170 0.000 528.450 4.000 ;
    END
  END axi_awaddr_o[17]
  PIN axi_awaddr_o[18]
    DIRECTION OUTPUT ;
    USE SIGNAL ;
    ANTENNADIFFAREA 0.891000 ;
    PORT
      LAYER met2 ;
        RECT 553.930 0.000 554.210 4.000 ;
    END
  END axi_awaddr_o[18]
  PIN axi_awaddr_o[19]
    DIRECTION OUTPUT ;
    USE SIGNAL ;
    ANTENNADIFFAREA 0.891000 ;
    PORT
      LAYER met2 ;
        RECT 537.830 0.000 538.110 4.000 ;
    END
  END axi_awaddr_o[19]
  PIN axi_awaddr_o[1]
    DIRECTION OUTPUT ;
    USE SIGNAL ;
    PORT
      LAYER met3 ;
        RECT 3596.000 1764.640 3600.000 1765.240 ;
    END
  END axi_awaddr_o[1]
  PIN axi_awaddr_o[20]
    DIRECTION OUTPUT ;
    USE SIGNAL ;
    ANTENNADIFFAREA 0.891000 ;
    PORT
      LAYER met2 ;
        RECT 470.210 0.000 470.490 4.000 ;
    END
  END axi_awaddr_o[20]
  PIN axi_awaddr_o[21]
    DIRECTION OUTPUT ;
    USE SIGNAL ;
    ANTENNADIFFAREA 0.891000 ;
    PORT
      LAYER met2 ;
        RECT 421.910 0.000 422.190 4.000 ;
    END
  END axi_awaddr_o[21]
  PIN axi_awaddr_o[22]
    DIRECTION OUTPUT ;
    USE SIGNAL ;
    ANTENNADIFFAREA 0.891000 ;
    PORT
      LAYER met2 ;
        RECT 425.130 0.000 425.410 4.000 ;
    END
  END axi_awaddr_o[22]
  PIN axi_awaddr_o[23]
    DIRECTION OUTPUT ;
    USE SIGNAL ;
    ANTENNADIFFAREA 0.891000 ;
    PORT
      LAYER met2 ;
        RECT 450.890 0.000 451.170 4.000 ;
    END
  END axi_awaddr_o[23]
  PIN axi_awaddr_o[24]
    DIRECTION OUTPUT ;
    USE SIGNAL ;
    ANTENNADIFFAREA 0.891000 ;
    PORT
      LAYER met2 ;
        RECT 431.570 0.000 431.850 4.000 ;
    END
  END axi_awaddr_o[24]
  PIN axi_awaddr_o[25]
    DIRECTION OUTPUT ;
    USE SIGNAL ;
    ANTENNADIFFAREA 0.891000 ;
    PORT
      LAYER met2 ;
        RECT 508.850 0.000 509.130 4.000 ;
    END
  END axi_awaddr_o[25]
  PIN axi_awaddr_o[26]
    DIRECTION OUTPUT ;
    USE SIGNAL ;
    ANTENNADIFFAREA 0.891000 ;
    PORT
      LAYER met2 ;
        RECT 1503.830 0.000 1504.110 4.000 ;
    END
  END axi_awaddr_o[26]
  PIN axi_awaddr_o[27]
    DIRECTION OUTPUT ;
    USE SIGNAL ;
    ANTENNADIFFAREA 0.891000 ;
    PORT
      LAYER met2 ;
        RECT 476.650 0.000 476.930 4.000 ;
    END
  END axi_awaddr_o[27]
  PIN axi_awaddr_o[28]
    DIRECTION OUTPUT ;
    USE SIGNAL ;
    ANTENNADIFFAREA 0.891000 ;
    PORT
      LAYER met2 ;
        RECT 499.190 0.000 499.470 4.000 ;
    END
  END axi_awaddr_o[28]
  PIN axi_awaddr_o[29]
    DIRECTION OUTPUT ;
    USE SIGNAL ;
    ANTENNADIFFAREA 0.891000 ;
    PORT
      LAYER met2 ;
        RECT 573.250 0.000 573.530 4.000 ;
    END
  END axi_awaddr_o[29]
  PIN axi_awaddr_o[2]
    DIRECTION OUTPUT ;
    USE SIGNAL ;
    ANTENNADIFFAREA 0.891000 ;
    PORT
      LAYER met2 ;
        RECT 1339.610 1796.000 1339.890 1800.000 ;
    END
  END axi_awaddr_o[2]
  PIN axi_awaddr_o[30]
    DIRECTION OUTPUT ;
    USE SIGNAL ;
    ANTENNADIFFAREA 0.891000 ;
    PORT
      LAYER met2 ;
        RECT 566.810 0.000 567.090 4.000 ;
    END
  END axi_awaddr_o[30]
  PIN axi_awaddr_o[31]
    DIRECTION OUTPUT ;
    USE SIGNAL ;
    ANTENNADIFFAREA 0.891000 ;
    PORT
      LAYER met2 ;
        RECT 518.510 0.000 518.790 4.000 ;
    END
  END axi_awaddr_o[31]
  PIN axi_awaddr_o[3]
    DIRECTION OUTPUT ;
    USE SIGNAL ;
    ANTENNADIFFAREA 0.891000 ;
    PORT
      LAYER met2 ;
        RECT 1336.390 1796.000 1336.670 1800.000 ;
    END
  END axi_awaddr_o[3]
  PIN axi_awaddr_o[4]
    DIRECTION OUTPUT ;
    USE SIGNAL ;
    ANTENNADIFFAREA 0.891000 ;
    PORT
      LAYER met2 ;
        RECT 834.070 1796.000 834.350 1800.000 ;
    END
  END axi_awaddr_o[4]
  PIN axi_awaddr_o[5]
    DIRECTION OUTPUT ;
    USE SIGNAL ;
    ANTENNADIFFAREA 0.891000 ;
    PORT
      LAYER met2 ;
        RECT 821.190 1796.000 821.470 1800.000 ;
    END
  END axi_awaddr_o[5]
  PIN axi_awaddr_o[6]
    DIRECTION OUTPUT ;
    USE SIGNAL ;
    ANTENNADIFFAREA 0.891000 ;
    PORT
      LAYER met2 ;
        RECT 827.630 1796.000 827.910 1800.000 ;
    END
  END axi_awaddr_o[6]
  PIN axi_awaddr_o[7]
    DIRECTION OUTPUT ;
    USE SIGNAL ;
    ANTENNADIFFAREA 0.891000 ;
    PORT
      LAYER met2 ;
        RECT 837.290 1796.000 837.570 1800.000 ;
    END
  END axi_awaddr_o[7]
  PIN axi_awaddr_o[8]
    DIRECTION OUTPUT ;
    USE SIGNAL ;
    ANTENNADIFFAREA 0.891000 ;
    PORT
      LAYER met2 ;
        RECT 824.410 1796.000 824.690 1800.000 ;
    END
  END axi_awaddr_o[8]
  PIN axi_awaddr_o[9]
    DIRECTION OUTPUT ;
    USE SIGNAL ;
    ANTENNADIFFAREA 0.891000 ;
    PORT
      LAYER met2 ;
        RECT 830.850 1796.000 831.130 1800.000 ;
    END
  END axi_awaddr_o[9]
  PIN axi_awburst_o[0]
    DIRECTION OUTPUT ;
    USE SIGNAL ;
    PORT
      LAYER met2 ;
        RECT 3078.410 1796.000 3078.690 1800.000 ;
    END
  END axi_awburst_o[0]
  PIN axi_awburst_o[1]
    DIRECTION OUTPUT ;
    USE SIGNAL ;
    PORT
      LAYER met2 ;
        RECT 3355.330 1796.000 3355.610 1800.000 ;
    END
  END axi_awburst_o[1]
  PIN axi_awlen_o[0]
    DIRECTION OUTPUT ;
    USE SIGNAL ;
    ANTENNADIFFAREA 0.891000 ;
    PORT
      LAYER met2 ;
        RECT 1326.730 0.000 1327.010 4.000 ;
    END
  END axi_awlen_o[0]
  PIN axi_awlen_o[1]
    DIRECTION OUTPUT ;
    USE SIGNAL ;
    ANTENNADIFFAREA 0.891000 ;
    PORT
      LAYER met2 ;
        RECT 1329.950 0.000 1330.230 4.000 ;
    END
  END axi_awlen_o[1]
  PIN axi_awlen_o[2]
    DIRECTION OUTPUT ;
    USE SIGNAL ;
    PORT
      LAYER met2 ;
        RECT 3004.350 1796.000 3004.630 1800.000 ;
    END
  END axi_awlen_o[2]
  PIN axi_awlen_o[3]
    DIRECTION OUTPUT ;
    USE SIGNAL ;
    PORT
      LAYER met2 ;
        RECT 2608.290 1796.000 2608.570 1800.000 ;
    END
  END axi_awlen_o[3]
  PIN axi_awlen_o[4]
    DIRECTION OUTPUT ;
    USE SIGNAL ;
    PORT
      LAYER met2 ;
        RECT 3313.470 1796.000 3313.750 1800.000 ;
    END
  END axi_awlen_o[4]
  PIN axi_awlen_o[5]
    DIRECTION OUTPUT ;
    USE SIGNAL ;
    PORT
      LAYER met2 ;
        RECT 2257.310 1796.000 2257.590 1800.000 ;
    END
  END axi_awlen_o[5]
  PIN axi_awlen_o[6]
    DIRECTION OUTPUT ;
    USE SIGNAL ;
    PORT
      LAYER met2 ;
        RECT 3371.430 1796.000 3371.710 1800.000 ;
    END
  END axi_awlen_o[6]
  PIN axi_awlen_o[7]
    DIRECTION OUTPUT ;
    USE SIGNAL ;
    PORT
      LAYER met2 ;
        RECT 2881.990 1796.000 2882.270 1800.000 ;
    END
  END axi_awlen_o[7]
  PIN axi_awready_i
    DIRECTION INPUT ;
    USE SIGNAL ;
    ANTENNAGATEAREA 0.560700 ;
    ANTENNADIFFAREA 0.434700 ;
    PORT
      LAYER met2 ;
        RECT 1281.650 0.000 1281.930 4.000 ;
    END
  END axi_awready_i
  PIN axi_awsize_o[0]
    DIRECTION OUTPUT ;
    USE SIGNAL ;
    PORT
      LAYER met2 ;
        RECT 2997.910 1796.000 2998.190 1800.000 ;
    END
  END axi_awsize_o[0]
  PIN axi_awsize_o[1]
    DIRECTION OUTPUT ;
    USE SIGNAL ;
    PORT
      LAYER met3 ;
        RECT 3596.000 1771.440 3600.000 1772.040 ;
    END
  END axi_awsize_o[1]
  PIN axi_awsize_o[2]
    DIRECTION OUTPUT ;
    USE SIGNAL ;
    PORT
      LAYER met2 ;
        RECT 3377.870 1796.000 3378.150 1800.000 ;
    END
  END axi_awsize_o[2]
  PIN axi_awvalid_o
    DIRECTION OUTPUT ;
    USE SIGNAL ;
    ANTENNADIFFAREA 0.891000 ;
    PORT
      LAYER met2 ;
        RECT 1275.210 0.000 1275.490 4.000 ;
    END
  END axi_awvalid_o
  PIN axi_bready_o
    DIRECTION OUTPUT ;
    USE SIGNAL ;
    ANTENNADIFFAREA 0.891000 ;
    PORT
      LAYER met2 ;
        RECT 1291.310 0.000 1291.590 4.000 ;
    END
  END axi_bready_o
  PIN axi_bresp_i[0]
    DIRECTION INPUT ;
    USE SIGNAL ;
    ANTENNAGATEAREA 0.560700 ;
    ANTENNADIFFAREA 0.434700 ;
    PORT
      LAYER met2 ;
        RECT 1288.090 1796.000 1288.370 1800.000 ;
    END
  END axi_bresp_i[0]
  PIN axi_bresp_i[1]
    DIRECTION INPUT ;
    USE SIGNAL ;
    ANTENNAGATEAREA 0.560700 ;
    ANTENNADIFFAREA 0.434700 ;
    PORT
      LAYER met2 ;
        RECT 1284.870 1796.000 1285.150 1800.000 ;
    END
  END axi_bresp_i[1]
  PIN axi_bvalid_i
    DIRECTION INPUT ;
    USE SIGNAL ;
    ANTENNAGATEAREA 0.560700 ;
    ANTENNADIFFAREA 0.434700 ;
    PORT
      LAYER met2 ;
        RECT 1288.090 0.000 1288.370 4.000 ;
    END
  END axi_bvalid_i
  PIN axi_rdata_i[0]
    DIRECTION INPUT ;
    USE SIGNAL ;
    ANTENNAGATEAREA 0.560700 ;
    ANTENNADIFFAREA 0.434700 ;
    PORT
      LAYER met2 ;
        RECT 1313.850 0.000 1314.130 4.000 ;
    END
  END axi_rdata_i[0]
  PIN axi_rdata_i[10]
    DIRECTION INPUT ;
    USE SIGNAL ;
    ANTENNAGATEAREA 0.560700 ;
    ANTENNADIFFAREA 0.434700 ;
    PORT
      LAYER met2 ;
        RECT 1378.250 0.000 1378.530 4.000 ;
    END
  END axi_rdata_i[10]
  PIN axi_rdata_i[11]
    DIRECTION INPUT ;
    USE SIGNAL ;
    ANTENNAGATEAREA 0.560700 ;
    ANTENNADIFFAREA 0.434700 ;
    PORT
      LAYER met2 ;
        RECT 1339.610 0.000 1339.890 4.000 ;
    END
  END axi_rdata_i[11]
  PIN axi_rdata_i[12]
    DIRECTION INPUT ;
    USE SIGNAL ;
    ANTENNAGATEAREA 0.560700 ;
    ANTENNADIFFAREA 0.434700 ;
    PORT
      LAYER met2 ;
        RECT 1346.050 0.000 1346.330 4.000 ;
    END
  END axi_rdata_i[12]
  PIN axi_rdata_i[13]
    DIRECTION INPUT ;
    USE SIGNAL ;
    ANTENNAGATEAREA 0.560700 ;
    ANTENNADIFFAREA 0.434700 ;
    PORT
      LAYER met2 ;
        RECT 1304.190 0.000 1304.470 4.000 ;
    END
  END axi_rdata_i[13]
  PIN axi_rdata_i[14]
    DIRECTION INPUT ;
    USE SIGNAL ;
    ANTENNAGATEAREA 0.560700 ;
    ANTENNADIFFAREA 0.434700 ;
    PORT
      LAYER met2 ;
        RECT 1336.390 0.000 1336.670 4.000 ;
    END
  END axi_rdata_i[14]
  PIN axi_rdata_i[15]
    DIRECTION INPUT ;
    USE SIGNAL ;
    ANTENNAGATEAREA 0.560700 ;
    ANTENNADIFFAREA 0.434700 ;
    PORT
      LAYER met2 ;
        RECT 1420.110 0.000 1420.390 4.000 ;
    END
  END axi_rdata_i[15]
  PIN axi_rdata_i[16]
    DIRECTION INPUT ;
    USE SIGNAL ;
    ANTENNAGATEAREA 0.560700 ;
    ANTENNADIFFAREA 0.434700 ;
    PORT
      LAYER met2 ;
        RECT 1323.510 0.000 1323.790 4.000 ;
    END
  END axi_rdata_i[16]
  PIN axi_rdata_i[17]
    DIRECTION INPUT ;
    USE SIGNAL ;
    ANTENNAGATEAREA 0.995400 ;
    ANTENNADIFFAREA 0.869400 ;
    PORT
      LAYER met2 ;
        RECT 1362.150 0.000 1362.430 4.000 ;
    END
  END axi_rdata_i[17]
  PIN axi_rdata_i[18]
    DIRECTION INPUT ;
    USE SIGNAL ;
    ANTENNAGATEAREA 0.560700 ;
    ANTENNADIFFAREA 0.434700 ;
    PORT
      LAYER met2 ;
        RECT 1333.170 0.000 1333.450 4.000 ;
    END
  END axi_rdata_i[18]
  PIN axi_rdata_i[19]
    DIRECTION INPUT ;
    USE SIGNAL ;
    ANTENNAGATEAREA 0.560700 ;
    ANTENNADIFFAREA 0.434700 ;
    PORT
      LAYER met2 ;
        RECT 1342.830 0.000 1343.110 4.000 ;
    END
  END axi_rdata_i[19]
  PIN axi_rdata_i[1]
    DIRECTION INPUT ;
    USE SIGNAL ;
    ANTENNAGATEAREA 0.560700 ;
    ANTENNADIFFAREA 0.434700 ;
    PORT
      LAYER met2 ;
        RECT 1358.930 0.000 1359.210 4.000 ;
    END
  END axi_rdata_i[1]
  PIN axi_rdata_i[20]
    DIRECTION INPUT ;
    USE SIGNAL ;
    ANTENNAGATEAREA 0.560700 ;
    ANTENNADIFFAREA 0.434700 ;
    PORT
      LAYER met2 ;
        RECT 1349.270 0.000 1349.550 4.000 ;
    END
  END axi_rdata_i[20]
  PIN axi_rdata_i[21]
    DIRECTION INPUT ;
    USE SIGNAL ;
    ANTENNAGATEAREA 0.560700 ;
    ANTENNADIFFAREA 0.434700 ;
    PORT
      LAYER met2 ;
        RECT 1416.890 0.000 1417.170 4.000 ;
    END
  END axi_rdata_i[21]
  PIN axi_rdata_i[22]
    DIRECTION INPUT ;
    USE SIGNAL ;
    ANTENNAGATEAREA 0.560700 ;
    ANTENNADIFFAREA 0.434700 ;
    PORT
      LAYER met2 ;
        RECT 1355.710 0.000 1355.990 4.000 ;
    END
  END axi_rdata_i[22]
  PIN axi_rdata_i[23]
    DIRECTION INPUT ;
    USE SIGNAL ;
    ANTENNAGATEAREA 0.560700 ;
    ANTENNADIFFAREA 0.434700 ;
    PORT
      LAYER met2 ;
        RECT 1352.490 0.000 1352.770 4.000 ;
    END
  END axi_rdata_i[23]
  PIN axi_rdata_i[24]
    DIRECTION INPUT ;
    USE SIGNAL ;
    ANTENNAGATEAREA 0.560700 ;
    ANTENNADIFFAREA 0.434700 ;
    PORT
      LAYER met2 ;
        RECT 1384.690 0.000 1384.970 4.000 ;
    END
  END axi_rdata_i[24]
  PIN axi_rdata_i[25]
    DIRECTION INPUT ;
    USE SIGNAL ;
    ANTENNAGATEAREA 0.560700 ;
    ANTENNADIFFAREA 0.434700 ;
    PORT
      LAYER met2 ;
        RECT 1387.910 0.000 1388.190 4.000 ;
    END
  END axi_rdata_i[25]
  PIN axi_rdata_i[26]
    DIRECTION INPUT ;
    USE SIGNAL ;
    ANTENNAGATEAREA 0.560700 ;
    ANTENNADIFFAREA 0.434700 ;
    PORT
      LAYER met2 ;
        RECT 1368.590 0.000 1368.870 4.000 ;
    END
  END axi_rdata_i[26]
  PIN axi_rdata_i[27]
    DIRECTION INPUT ;
    USE SIGNAL ;
    ANTENNAGATEAREA 0.560700 ;
    ANTENNADIFFAREA 0.434700 ;
    PORT
      LAYER met2 ;
        RECT 1365.370 0.000 1365.650 4.000 ;
    END
  END axi_rdata_i[27]
  PIN axi_rdata_i[28]
    DIRECTION INPUT ;
    USE SIGNAL ;
    ANTENNAGATEAREA 0.995400 ;
    ANTENNADIFFAREA 0.869400 ;
    PORT
      LAYER met2 ;
        RECT 1375.030 0.000 1375.310 4.000 ;
    END
  END axi_rdata_i[28]
  PIN axi_rdata_i[29]
    DIRECTION INPUT ;
    USE SIGNAL ;
    ANTENNAGATEAREA 0.560700 ;
    ANTENNADIFFAREA 0.434700 ;
    PORT
      LAYER met2 ;
        RECT 1371.810 0.000 1372.090 4.000 ;
    END
  END axi_rdata_i[29]
  PIN axi_rdata_i[2]
    DIRECTION INPUT ;
    USE SIGNAL ;
    ANTENNAGATEAREA 0.560700 ;
    ANTENNADIFFAREA 0.434700 ;
    PORT
      LAYER met2 ;
        RECT 1381.470 0.000 1381.750 4.000 ;
    END
  END axi_rdata_i[2]
  PIN axi_rdata_i[30]
    DIRECTION INPUT ;
    USE SIGNAL ;
    ANTENNAGATEAREA 0.560700 ;
    ANTENNADIFFAREA 0.434700 ;
    PORT
      LAYER met2 ;
        RECT 1410.450 0.000 1410.730 4.000 ;
    END
  END axi_rdata_i[30]
  PIN axi_rdata_i[31]
    DIRECTION INPUT ;
    USE SIGNAL ;
    ANTENNAGATEAREA 0.560700 ;
    ANTENNADIFFAREA 0.434700 ;
    PORT
      LAYER met2 ;
        RECT 1413.670 0.000 1413.950 4.000 ;
    END
  END axi_rdata_i[31]
  PIN axi_rdata_i[3]
    DIRECTION INPUT ;
    USE SIGNAL ;
    ANTENNAGATEAREA 0.560700 ;
    ANTENNADIFFAREA 0.434700 ;
    PORT
      LAYER met2 ;
        RECT 1404.010 0.000 1404.290 4.000 ;
    END
  END axi_rdata_i[3]
  PIN axi_rdata_i[4]
    DIRECTION INPUT ;
    USE SIGNAL ;
    ANTENNAGATEAREA 0.560700 ;
    ANTENNADIFFAREA 0.434700 ;
    PORT
      LAYER met2 ;
        RECT 1394.350 0.000 1394.630 4.000 ;
    END
  END axi_rdata_i[4]
  PIN axi_rdata_i[5]
    DIRECTION INPUT ;
    USE SIGNAL ;
    ANTENNAGATEAREA 0.560700 ;
    ANTENNADIFFAREA 0.434700 ;
    PORT
      LAYER met2 ;
        RECT 1391.130 0.000 1391.410 4.000 ;
    END
  END axi_rdata_i[5]
  PIN axi_rdata_i[6]
    DIRECTION INPUT ;
    USE SIGNAL ;
    ANTENNAGATEAREA 0.560700 ;
    ANTENNADIFFAREA 0.434700 ;
    PORT
      LAYER met2 ;
        RECT 1400.790 0.000 1401.070 4.000 ;
    END
  END axi_rdata_i[6]
  PIN axi_rdata_i[7]
    DIRECTION INPUT ;
    USE SIGNAL ;
    ANTENNAGATEAREA 0.995400 ;
    ANTENNADIFFAREA 0.869400 ;
    PORT
      LAYER met2 ;
        RECT 1397.570 0.000 1397.850 4.000 ;
    END
  END axi_rdata_i[7]
  PIN axi_rdata_i[8]
    DIRECTION INPUT ;
    USE SIGNAL ;
    ANTENNAGATEAREA 0.560700 ;
    ANTENNADIFFAREA 0.434700 ;
    PORT
      LAYER met2 ;
        RECT 1407.230 0.000 1407.510 4.000 ;
    END
  END axi_rdata_i[8]
  PIN axi_rdata_i[9]
    DIRECTION INPUT ;
    USE SIGNAL ;
    ANTENNAGATEAREA 0.560700 ;
    ANTENNADIFFAREA 0.434700 ;
    PORT
      LAYER met2 ;
        RECT 1429.770 0.000 1430.050 4.000 ;
    END
  END axi_rdata_i[9]
  PIN axi_rlast_i
    DIRECTION INPUT ;
    USE SIGNAL ;
    ANTENNAGATEAREA 0.560700 ;
    ANTENNADIFFAREA 0.434700 ;
    PORT
      LAYER met2 ;
        RECT 647.310 0.000 647.590 4.000 ;
    END
  END axi_rlast_i
  PIN axi_rready_o
    DIRECTION OUTPUT ;
    USE SIGNAL ;
    PORT
      LAYER met3 ;
        RECT 3596.000 1757.840 3600.000 1758.440 ;
    END
  END axi_rready_o
  PIN axi_rresp_i[0]
    DIRECTION INPUT ;
    USE SIGNAL ;
    ANTENNAGATEAREA 0.560700 ;
    ANTENNADIFFAREA 0.434700 ;
    PORT
      LAYER met2 ;
        RECT 1317.070 0.000 1317.350 4.000 ;
    END
  END axi_rresp_i[0]
  PIN axi_rresp_i[1]
    DIRECTION INPUT ;
    USE SIGNAL ;
    ANTENNAGATEAREA 0.560700 ;
    ANTENNADIFFAREA 0.434700 ;
    PORT
      LAYER met2 ;
        RECT 1320.290 0.000 1320.570 4.000 ;
    END
  END axi_rresp_i[1]
  PIN axi_rvalid_i
    DIRECTION INPUT ;
    USE SIGNAL ;
    ANTENNAGATEAREA 0.560700 ;
    ANTENNADIFFAREA 0.434700 ;
    PORT
      LAYER met2 ;
        RECT 1310.630 0.000 1310.910 4.000 ;
    END
  END axi_rvalid_i
  PIN axi_wdata_o[0]
    DIRECTION OUTPUT ;
    USE SIGNAL ;
    ANTENNADIFFAREA 0.891000 ;
    PORT
      LAYER met2 ;
        RECT 1986.830 0.000 1987.110 4.000 ;
    END
  END axi_wdata_o[0]
  PIN axi_wdata_o[10]
    DIRECTION OUTPUT ;
    USE SIGNAL ;
    ANTENNADIFFAREA 0.891000 ;
    PORT
      LAYER met2 ;
        RECT 1996.490 0.000 1996.770 4.000 ;
    END
  END axi_wdata_o[10]
  PIN axi_wdata_o[11]
    DIRECTION OUTPUT ;
    USE SIGNAL ;
    ANTENNADIFFAREA 0.891000 ;
    PORT
      LAYER met2 ;
        RECT 2125.290 0.000 2125.570 4.000 ;
    END
  END axi_wdata_o[11]
  PIN axi_wdata_o[12]
    DIRECTION OUTPUT ;
    USE SIGNAL ;
    ANTENNADIFFAREA 0.891000 ;
    PORT
      LAYER met2 ;
        RECT 1993.270 0.000 1993.550 4.000 ;
    END
  END axi_wdata_o[12]
  PIN axi_wdata_o[13]
    DIRECTION OUTPUT ;
    USE SIGNAL ;
    ANTENNADIFFAREA 0.891000 ;
    PORT
      LAYER met2 ;
        RECT 2002.930 0.000 2003.210 4.000 ;
    END
  END axi_wdata_o[13]
  PIN axi_wdata_o[14]
    DIRECTION OUTPUT ;
    USE SIGNAL ;
    ANTENNADIFFAREA 0.891000 ;
    PORT
      LAYER met2 ;
        RECT 1999.710 0.000 1999.990 4.000 ;
    END
  END axi_wdata_o[14]
  PIN axi_wdata_o[15]
    DIRECTION OUTPUT ;
    USE SIGNAL ;
    ANTENNADIFFAREA 0.891000 ;
    PORT
      LAYER met2 ;
        RECT 1899.890 1796.000 1900.170 1800.000 ;
    END
  END axi_wdata_o[15]
  PIN axi_wdata_o[16]
    DIRECTION OUTPUT ;
    USE SIGNAL ;
    ANTENNADIFFAREA 0.891000 ;
    PORT
      LAYER met2 ;
        RECT 2096.310 1796.000 2096.590 1800.000 ;
    END
  END axi_wdata_o[16]
  PIN axi_wdata_o[17]
    DIRECTION OUTPUT ;
    USE SIGNAL ;
    ANTENNADIFFAREA 0.891000 ;
    PORT
      LAYER met2 ;
        RECT 1996.490 1796.000 1996.770 1800.000 ;
    END
  END axi_wdata_o[17]
  PIN axi_wdata_o[18]
    DIRECTION OUTPUT ;
    USE SIGNAL ;
    ANTENNADIFFAREA 0.891000 ;
    PORT
      LAYER met2 ;
        RECT 2105.970 1796.000 2106.250 1800.000 ;
    END
  END axi_wdata_o[18]
  PIN axi_wdata_o[19]
    DIRECTION OUTPUT ;
    USE SIGNAL ;
    ANTENNADIFFAREA 0.891000 ;
    PORT
      LAYER met2 ;
        RECT 2118.850 1796.000 2119.130 1800.000 ;
    END
  END axi_wdata_o[19]
  PIN axi_wdata_o[1]
    DIRECTION OUTPUT ;
    USE SIGNAL ;
    ANTENNADIFFAREA 0.891000 ;
    PORT
      LAYER met2 ;
        RECT 1957.850 0.000 1958.130 4.000 ;
    END
  END axi_wdata_o[1]
  PIN axi_wdata_o[20]
    DIRECTION OUTPUT ;
    USE SIGNAL ;
    ANTENNADIFFAREA 0.891000 ;
    PORT
      LAYER met2 ;
        RECT 1970.730 1796.000 1971.010 1800.000 ;
    END
  END axi_wdata_o[20]
  PIN axi_wdata_o[21]
    DIRECTION OUTPUT ;
    USE SIGNAL ;
    ANTENNADIFFAREA 0.891000 ;
    PORT
      LAYER met2 ;
        RECT 1912.770 1796.000 1913.050 1800.000 ;
    END
  END axi_wdata_o[21]
  PIN axi_wdata_o[22]
    DIRECTION OUTPUT ;
    USE SIGNAL ;
    ANTENNADIFFAREA 0.891000 ;
    PORT
      LAYER met2 ;
        RECT 2122.070 1796.000 2122.350 1800.000 ;
    END
  END axi_wdata_o[22]
  PIN axi_wdata_o[23]
    DIRECTION OUTPUT ;
    USE SIGNAL ;
    ANTENNADIFFAREA 0.891000 ;
    PORT
      LAYER met2 ;
        RECT 2109.190 1796.000 2109.470 1800.000 ;
    END
  END axi_wdata_o[23]
  PIN axi_wdata_o[24]
    DIRECTION OUTPUT ;
    USE SIGNAL ;
    ANTENNADIFFAREA 0.891000 ;
    PORT
      LAYER met2 ;
        RECT 1944.970 1796.000 1945.250 1800.000 ;
    END
  END axi_wdata_o[24]
  PIN axi_wdata_o[25]
    DIRECTION OUTPUT ;
    USE SIGNAL ;
    ANTENNADIFFAREA 0.891000 ;
    PORT
      LAYER met2 ;
        RECT 1932.090 0.000 1932.370 4.000 ;
    END
  END axi_wdata_o[25]
  PIN axi_wdata_o[26]
    DIRECTION OUTPUT ;
    USE SIGNAL ;
    ANTENNADIFFAREA 0.891000 ;
    PORT
      LAYER met2 ;
        RECT 1893.450 0.000 1893.730 4.000 ;
    END
  END axi_wdata_o[26]
  PIN axi_wdata_o[27]
    DIRECTION OUTPUT ;
    USE SIGNAL ;
    ANTENNADIFFAREA 0.891000 ;
    PORT
      LAYER met2 ;
        RECT 1890.230 1796.000 1890.510 1800.000 ;
    END
  END axi_wdata_o[27]
  PIN axi_wdata_o[28]
    DIRECTION OUTPUT ;
    USE SIGNAL ;
    ANTENNADIFFAREA 0.891000 ;
    PORT
      LAYER met2 ;
        RECT 1909.550 0.000 1909.830 4.000 ;
    END
  END axi_wdata_o[28]
  PIN axi_wdata_o[29]
    DIRECTION OUTPUT ;
    USE SIGNAL ;
    ANTENNADIFFAREA 0.891000 ;
    PORT
      LAYER met2 ;
        RECT 1861.250 0.000 1861.530 4.000 ;
    END
  END axi_wdata_o[29]
  PIN axi_wdata_o[2]
    DIRECTION OUTPUT ;
    USE SIGNAL ;
    ANTENNADIFFAREA 0.891000 ;
    PORT
      LAYER met2 ;
        RECT 1983.610 0.000 1983.890 4.000 ;
    END
  END axi_wdata_o[2]
  PIN axi_wdata_o[30]
    DIRECTION OUTPUT ;
    USE SIGNAL ;
    ANTENNADIFFAREA 0.891000 ;
    PORT
      LAYER met2 ;
        RECT 1928.870 0.000 1929.150 4.000 ;
    END
  END axi_wdata_o[30]
  PIN axi_wdata_o[31]
    DIRECTION OUTPUT ;
    USE SIGNAL ;
    ANTENNADIFFAREA 0.891000 ;
    PORT
      LAYER met2 ;
        RECT 1864.470 0.000 1864.750 4.000 ;
    END
  END axi_wdata_o[31]
  PIN axi_wdata_o[3]
    DIRECTION OUTPUT ;
    USE SIGNAL ;
    ANTENNADIFFAREA 0.891000 ;
    PORT
      LAYER met2 ;
        RECT 2051.230 0.000 2051.510 4.000 ;
    END
  END axi_wdata_o[3]
  PIN axi_wdata_o[4]
    DIRECTION OUTPUT ;
    USE SIGNAL ;
    ANTENNADIFFAREA 0.891000 ;
    PORT
      LAYER met2 ;
        RECT 2099.530 0.000 2099.810 4.000 ;
    END
  END axi_wdata_o[4]
  PIN axi_wdata_o[5]
    DIRECTION OUTPUT ;
    USE SIGNAL ;
    ANTENNADIFFAREA 0.891000 ;
    PORT
      LAYER met2 ;
        RECT 2076.990 0.000 2077.270 4.000 ;
    END
  END axi_wdata_o[5]
  PIN axi_wdata_o[6]
    DIRECTION OUTPUT ;
    USE SIGNAL ;
    ANTENNADIFFAREA 0.891000 ;
    PORT
      LAYER met2 ;
        RECT 2096.310 0.000 2096.590 4.000 ;
    END
  END axi_wdata_o[6]
  PIN axi_wdata_o[7]
    DIRECTION OUTPUT ;
    USE SIGNAL ;
    ANTENNADIFFAREA 0.891000 ;
    PORT
      LAYER met2 ;
        RECT 2012.590 0.000 2012.870 4.000 ;
    END
  END axi_wdata_o[7]
  PIN axi_wdata_o[8]
    DIRECTION OUTPUT ;
    USE SIGNAL ;
    ANTENNADIFFAREA 0.891000 ;
    PORT
      LAYER met2 ;
        RECT 2122.070 0.000 2122.350 4.000 ;
    END
  END axi_wdata_o[8]
  PIN axi_wdata_o[9]
    DIRECTION OUTPUT ;
    USE SIGNAL ;
    ANTENNADIFFAREA 0.891000 ;
    PORT
      LAYER met2 ;
        RECT 2118.850 0.000 2119.130 4.000 ;
    END
  END axi_wdata_o[9]
  PIN axi_wlast_o
    DIRECTION OUTPUT ;
    USE SIGNAL ;
    ANTENNADIFFAREA 0.891000 ;
    PORT
      LAYER met2 ;
        RECT 1307.410 0.000 1307.690 4.000 ;
    END
  END axi_wlast_o
  PIN axi_wready_i
    DIRECTION INPUT ;
    USE SIGNAL ;
    ANTENNAGATEAREA 0.560700 ;
    ANTENNADIFFAREA 0.434700 ;
    PORT
      LAYER met2 ;
        RECT 1297.750 0.000 1298.030 4.000 ;
    END
  END axi_wready_i
  PIN axi_wstrb_o[0]
    DIRECTION OUTPUT ;
    USE SIGNAL ;
    ANTENNADIFFAREA 0.891000 ;
    PORT
      LAYER met2 ;
        RECT 1548.910 0.000 1549.190 4.000 ;
    END
  END axi_wstrb_o[0]
  PIN axi_wstrb_o[1]
    DIRECTION OUTPUT ;
    USE SIGNAL ;
    ANTENNADIFFAREA 0.891000 ;
    PORT
      LAYER met2 ;
        RECT 1542.470 0.000 1542.750 4.000 ;
    END
  END axi_wstrb_o[1]
  PIN axi_wstrb_o[2]
    DIRECTION OUTPUT ;
    USE SIGNAL ;
    ANTENNADIFFAREA 0.891000 ;
    PORT
      LAYER met2 ;
        RECT 1497.390 1796.000 1497.670 1800.000 ;
    END
  END axi_wstrb_o[2]
  PIN axi_wstrb_o[3]
    DIRECTION OUTPUT ;
    USE SIGNAL ;
    ANTENNADIFFAREA 0.891000 ;
    PORT
      LAYER met2 ;
        RECT 1545.690 0.000 1545.970 4.000 ;
    END
  END axi_wstrb_o[3]
  PIN axi_wvalid_o
    DIRECTION OUTPUT ;
    USE SIGNAL ;
    ANTENNADIFFAREA 0.891000 ;
    PORT
      LAYER met2 ;
        RECT 1300.970 0.000 1301.250 4.000 ;
    END
  END axi_wvalid_o
  PIN clk_i
    DIRECTION INPUT ;
    USE SIGNAL ;
    ANTENNAGATEAREA 2.590800 ;
    ANTENNADIFFAREA 1.738800 ;
    PORT
      LAYER met2 ;
        RECT 132.110 0.000 132.390 4.000 ;
    END
  END clk_i
  PIN commit_insn_o[0]
    DIRECTION OUTPUT ;
    USE SIGNAL ;
    ANTENNADIFFAREA 0.891000 ;
    PORT
      LAYER met2 ;
        RECT 1700.250 1796.000 1700.530 1800.000 ;
    END
  END commit_insn_o[0]
  PIN commit_insn_o[10]
    DIRECTION OUTPUT ;
    USE SIGNAL ;
    ANTENNADIFFAREA 0.891000 ;
    PORT
      LAYER met2 ;
        RECT 1719.570 1796.000 1719.850 1800.000 ;
    END
  END commit_insn_o[10]
  PIN commit_insn_o[11]
    DIRECTION OUTPUT ;
    USE SIGNAL ;
    ANTENNADIFFAREA 0.891000 ;
    PORT
      LAYER met2 ;
        RECT 1661.610 1796.000 1661.890 1800.000 ;
    END
  END commit_insn_o[11]
  PIN commit_insn_o[12]
    DIRECTION OUTPUT ;
    USE SIGNAL ;
    ANTENNADIFFAREA 0.891000 ;
    PORT
      LAYER met2 ;
        RECT 1748.550 1796.000 1748.830 1800.000 ;
    END
  END commit_insn_o[12]
  PIN commit_insn_o[13]
    DIRECTION OUTPUT ;
    USE SIGNAL ;
    ANTENNADIFFAREA 0.891000 ;
    PORT
      LAYER met2 ;
        RECT 1629.410 1796.000 1629.690 1800.000 ;
    END
  END commit_insn_o[13]
  PIN commit_insn_o[14]
    DIRECTION OUTPUT ;
    USE SIGNAL ;
    ANTENNADIFFAREA 0.891000 ;
    PORT
      LAYER met2 ;
        RECT 1671.270 1796.000 1671.550 1800.000 ;
    END
  END commit_insn_o[14]
  PIN commit_insn_o[15]
    DIRECTION OUTPUT ;
    USE SIGNAL ;
    ANTENNADIFFAREA 0.891000 ;
    PORT
      LAYER met2 ;
        RECT 1677.710 1796.000 1677.990 1800.000 ;
    END
  END commit_insn_o[15]
  PIN commit_insn_o[16]
    DIRECTION OUTPUT ;
    USE SIGNAL ;
    ANTENNADIFFAREA 0.891000 ;
    PORT
      LAYER met2 ;
        RECT 1680.930 1796.000 1681.210 1800.000 ;
    END
  END commit_insn_o[16]
  PIN commit_insn_o[17]
    DIRECTION OUTPUT ;
    USE SIGNAL ;
    ANTENNADIFFAREA 0.891000 ;
    PORT
      LAYER met2 ;
        RECT 1597.210 1796.000 1597.490 1800.000 ;
    END
  END commit_insn_o[17]
  PIN commit_insn_o[18]
    DIRECTION OUTPUT ;
    USE SIGNAL ;
    ANTENNADIFFAREA 0.891000 ;
    PORT
      LAYER met2 ;
        RECT 1655.170 1796.000 1655.450 1800.000 ;
    END
  END commit_insn_o[18]
  PIN commit_insn_o[19]
    DIRECTION OUTPUT ;
    USE SIGNAL ;
    ANTENNADIFFAREA 0.891000 ;
    PORT
      LAYER met2 ;
        RECT 1668.050 1796.000 1668.330 1800.000 ;
    END
  END commit_insn_o[19]
  PIN commit_insn_o[1]
    DIRECTION OUTPUT ;
    USE SIGNAL ;
    ANTENNADIFFAREA 0.891000 ;
    PORT
      LAYER met2 ;
        RECT 1693.810 1796.000 1694.090 1800.000 ;
    END
  END commit_insn_o[1]
  PIN commit_insn_o[20]
    DIRECTION OUTPUT ;
    USE SIGNAL ;
    ANTENNADIFFAREA 0.891000 ;
    PORT
      LAYER met2 ;
        RECT 1709.910 1796.000 1710.190 1800.000 ;
    END
  END commit_insn_o[20]
  PIN commit_insn_o[21]
    DIRECTION OUTPUT ;
    USE SIGNAL ;
    ANTENNADIFFAREA 0.891000 ;
    PORT
      LAYER met2 ;
        RECT 1684.150 1796.000 1684.430 1800.000 ;
    END
  END commit_insn_o[21]
  PIN commit_insn_o[22]
    DIRECTION OUTPUT ;
    USE SIGNAL ;
    ANTENNADIFFAREA 0.891000 ;
    PORT
      LAYER met2 ;
        RECT 1658.390 1796.000 1658.670 1800.000 ;
    END
  END commit_insn_o[22]
  PIN commit_insn_o[23]
    DIRECTION OUTPUT ;
    USE SIGNAL ;
    ANTENNADIFFAREA 0.891000 ;
    PORT
      LAYER met2 ;
        RECT 1803.290 1796.000 1803.570 1800.000 ;
    END
  END commit_insn_o[23]
  PIN commit_insn_o[24]
    DIRECTION OUTPUT ;
    USE SIGNAL ;
    ANTENNADIFFAREA 0.891000 ;
    PORT
      LAYER met2 ;
        RECT 1639.070 1796.000 1639.350 1800.000 ;
    END
  END commit_insn_o[24]
  PIN commit_insn_o[25]
    DIRECTION OUTPUT ;
    USE SIGNAL ;
    ANTENNADIFFAREA 0.891000 ;
    PORT
      LAYER met2 ;
        RECT 1606.870 1796.000 1607.150 1800.000 ;
    END
  END commit_insn_o[25]
  PIN commit_insn_o[26]
    DIRECTION OUTPUT ;
    USE SIGNAL ;
    ANTENNADIFFAREA 0.891000 ;
    PORT
      LAYER met2 ;
        RECT 1648.730 1796.000 1649.010 1800.000 ;
    END
  END commit_insn_o[26]
  PIN commit_insn_o[27]
    DIRECTION OUTPUT ;
    USE SIGNAL ;
    ANTENNADIFFAREA 0.891000 ;
    PORT
      LAYER met2 ;
        RECT 1610.090 1796.000 1610.370 1800.000 ;
    END
  END commit_insn_o[27]
  PIN commit_insn_o[28]
    DIRECTION OUTPUT ;
    USE SIGNAL ;
    ANTENNADIFFAREA 0.891000 ;
    PORT
      LAYER met2 ;
        RECT 1577.890 1796.000 1578.170 1800.000 ;
    END
  END commit_insn_o[28]
  PIN commit_insn_o[29]
    DIRECTION OUTPUT ;
    USE SIGNAL ;
    ANTENNADIFFAREA 0.891000 ;
    PORT
      LAYER met2 ;
        RECT 1571.450 1796.000 1571.730 1800.000 ;
    END
  END commit_insn_o[29]
  PIN commit_insn_o[2]
    DIRECTION OUTPUT ;
    USE SIGNAL ;
    ANTENNADIFFAREA 0.891000 ;
    PORT
      LAYER met2 ;
        RECT 1790.410 1796.000 1790.690 1800.000 ;
    END
  END commit_insn_o[2]
  PIN commit_insn_o[30]
    DIRECTION OUTPUT ;
    USE SIGNAL ;
    ANTENNADIFFAREA 0.891000 ;
    PORT
      LAYER met2 ;
        RECT 1558.570 1796.000 1558.850 1800.000 ;
    END
  END commit_insn_o[30]
  PIN commit_insn_o[31]
    DIRECTION OUTPUT ;
    USE SIGNAL ;
    ANTENNADIFFAREA 0.891000 ;
    PORT
      LAYER met2 ;
        RECT 1713.130 1796.000 1713.410 1800.000 ;
    END
  END commit_insn_o[31]
  PIN commit_insn_o[3]
    DIRECTION OUTPUT ;
    USE SIGNAL ;
    ANTENNADIFFAREA 0.891000 ;
    PORT
      LAYER met2 ;
        RECT 1716.350 1796.000 1716.630 1800.000 ;
    END
  END commit_insn_o[3]
  PIN commit_insn_o[4]
    DIRECTION OUTPUT ;
    USE SIGNAL ;
    ANTENNADIFFAREA 0.891000 ;
    PORT
      LAYER met2 ;
        RECT 1742.110 1796.000 1742.390 1800.000 ;
    END
  END commit_insn_o[4]
  PIN commit_insn_o[5]
    DIRECTION OUTPUT ;
    USE SIGNAL ;
    ANTENNADIFFAREA 0.891000 ;
    PORT
      LAYER met2 ;
        RECT 1729.230 1796.000 1729.510 1800.000 ;
    END
  END commit_insn_o[5]
  PIN commit_insn_o[6]
    DIRECTION OUTPUT ;
    USE SIGNAL ;
    ANTENNADIFFAREA 0.891000 ;
    PORT
      LAYER met2 ;
        RECT 1690.590 1796.000 1690.870 1800.000 ;
    END
  END commit_insn_o[6]
  PIN commit_insn_o[7]
    DIRECTION OUTPUT ;
    USE SIGNAL ;
    ANTENNADIFFAREA 0.891000 ;
    PORT
      LAYER met2 ;
        RECT 1706.690 1796.000 1706.970 1800.000 ;
    END
  END commit_insn_o[7]
  PIN commit_insn_o[8]
    DIRECTION OUTPUT ;
    USE SIGNAL ;
    ANTENNADIFFAREA 0.891000 ;
    PORT
      LAYER met2 ;
        RECT 1674.490 1796.000 1674.770 1800.000 ;
    END
  END commit_insn_o[8]
  PIN commit_insn_o[9]
    DIRECTION OUTPUT ;
    USE SIGNAL ;
    ANTENNADIFFAREA 0.891000 ;
    PORT
      LAYER met2 ;
        RECT 1642.290 1796.000 1642.570 1800.000 ;
    END
  END commit_insn_o[9]
  PIN commit_pc_o[0]
    DIRECTION OUTPUT ;
    USE SIGNAL ;
    ANTENNADIFFAREA 0.891000 ;
    PORT
      LAYER met2 ;
        RECT 1880.570 1796.000 1880.850 1800.000 ;
    END
  END commit_pc_o[0]
  PIN commit_pc_o[10]
    DIRECTION OUTPUT ;
    USE SIGNAL ;
    ANTENNADIFFAREA 0.891000 ;
    PORT
      LAYER met2 ;
        RECT 1938.530 1796.000 1938.810 1800.000 ;
    END
  END commit_pc_o[10]
  PIN commit_pc_o[11]
    DIRECTION OUTPUT ;
    USE SIGNAL ;
    ANTENNADIFFAREA 0.891000 ;
    PORT
      LAYER met2 ;
        RECT 1954.630 1796.000 1954.910 1800.000 ;
    END
  END commit_pc_o[11]
  PIN commit_pc_o[12]
    DIRECTION OUTPUT ;
    USE SIGNAL ;
    ANTENNADIFFAREA 0.891000 ;
    PORT
      LAYER met2 ;
        RECT 1980.390 1796.000 1980.670 1800.000 ;
    END
  END commit_pc_o[12]
  PIN commit_pc_o[13]
    DIRECTION OUTPUT ;
    USE SIGNAL ;
    ANTENNADIFFAREA 0.891000 ;
    PORT
      LAYER met2 ;
        RECT 1928.870 1796.000 1929.150 1800.000 ;
    END
  END commit_pc_o[13]
  PIN commit_pc_o[14]
    DIRECTION OUTPUT ;
    USE SIGNAL ;
    ANTENNADIFFAREA 0.891000 ;
    PORT
      LAYER met2 ;
        RECT 1977.170 1796.000 1977.450 1800.000 ;
    END
  END commit_pc_o[14]
  PIN commit_pc_o[15]
    DIRECTION OUTPUT ;
    USE SIGNAL ;
    ANTENNADIFFAREA 0.891000 ;
    PORT
      LAYER met2 ;
        RECT 1951.410 1796.000 1951.690 1800.000 ;
    END
  END commit_pc_o[15]
  PIN commit_pc_o[16]
    DIRECTION OUTPUT ;
    USE SIGNAL ;
    ANTENNADIFFAREA 0.891000 ;
    PORT
      LAYER met2 ;
        RECT 1973.950 1796.000 1974.230 1800.000 ;
    END
  END commit_pc_o[16]
  PIN commit_pc_o[17]
    DIRECTION OUTPUT ;
    USE SIGNAL ;
    ANTENNADIFFAREA 0.891000 ;
    PORT
      LAYER met2 ;
        RECT 1932.090 1796.000 1932.370 1800.000 ;
    END
  END commit_pc_o[17]
  PIN commit_pc_o[18]
    DIRECTION OUTPUT ;
    USE SIGNAL ;
    ANTENNADIFFAREA 0.891000 ;
    PORT
      LAYER met2 ;
        RECT 2086.650 1796.000 2086.930 1800.000 ;
    END
  END commit_pc_o[18]
  PIN commit_pc_o[19]
    DIRECTION OUTPUT ;
    USE SIGNAL ;
    ANTENNADIFFAREA 0.891000 ;
    PORT
      LAYER met2 ;
        RECT 1835.490 1796.000 1835.770 1800.000 ;
    END
  END commit_pc_o[19]
  PIN commit_pc_o[1]
    DIRECTION OUTPUT ;
    USE SIGNAL ;
    ANTENNADIFFAREA 0.891000 ;
    PORT
      LAYER met2 ;
        RECT 1906.330 1796.000 1906.610 1800.000 ;
    END
  END commit_pc_o[1]
  PIN commit_pc_o[20]
    DIRECTION OUTPUT ;
    USE SIGNAL ;
    ANTENNADIFFAREA 0.891000 ;
    PORT
      LAYER met2 ;
        RECT 1922.430 1796.000 1922.710 1800.000 ;
    END
  END commit_pc_o[20]
  PIN commit_pc_o[21]
    DIRECTION OUTPUT ;
    USE SIGNAL ;
    ANTENNADIFFAREA 0.891000 ;
    PORT
      LAYER met2 ;
        RECT 2089.870 1796.000 2090.150 1800.000 ;
    END
  END commit_pc_o[21]
  PIN commit_pc_o[22]
    DIRECTION OUTPUT ;
    USE SIGNAL ;
    ANTENNADIFFAREA 0.891000 ;
    PORT
      LAYER met2 ;
        RECT 1848.370 1796.000 1848.650 1800.000 ;
    END
  END commit_pc_o[22]
  PIN commit_pc_o[23]
    DIRECTION OUTPUT ;
    USE SIGNAL ;
    ANTENNADIFFAREA 0.891000 ;
    PORT
      LAYER met2 ;
        RECT 1935.310 1796.000 1935.590 1800.000 ;
    END
  END commit_pc_o[23]
  PIN commit_pc_o[24]
    DIRECTION OUTPUT ;
    USE SIGNAL ;
    ANTENNADIFFAREA 0.891000 ;
    PORT
      LAYER met2 ;
        RECT 1838.710 1796.000 1838.990 1800.000 ;
    END
  END commit_pc_o[24]
  PIN commit_pc_o[25]
    DIRECTION OUTPUT ;
    USE SIGNAL ;
    ANTENNADIFFAREA 0.891000 ;
    PORT
      LAYER met2 ;
        RECT 1861.250 1796.000 1861.530 1800.000 ;
    END
  END commit_pc_o[25]
  PIN commit_pc_o[26]
    DIRECTION OUTPUT ;
    USE SIGNAL ;
    ANTENNADIFFAREA 0.891000 ;
    PORT
      LAYER met2 ;
        RECT 1864.470 1796.000 1864.750 1800.000 ;
    END
  END commit_pc_o[26]
  PIN commit_pc_o[27]
    DIRECTION OUTPUT ;
    USE SIGNAL ;
    ANTENNADIFFAREA 0.891000 ;
    PORT
      LAYER met2 ;
        RECT 1851.590 1796.000 1851.870 1800.000 ;
    END
  END commit_pc_o[27]
  PIN commit_pc_o[28]
    DIRECTION OUTPUT ;
    USE SIGNAL ;
    ANTENNADIFFAREA 0.891000 ;
    PORT
      LAYER met2 ;
        RECT 1896.670 1796.000 1896.950 1800.000 ;
    END
  END commit_pc_o[28]
  PIN commit_pc_o[29]
    DIRECTION OUTPUT ;
    USE SIGNAL ;
    ANTENNADIFFAREA 0.891000 ;
    PORT
      LAYER met2 ;
        RECT 1841.930 1796.000 1842.210 1800.000 ;
    END
  END commit_pc_o[29]
  PIN commit_pc_o[2]
    DIRECTION OUTPUT ;
    USE SIGNAL ;
    ANTENNADIFFAREA 0.891000 ;
    PORT
      LAYER met2 ;
        RECT 1919.210 1796.000 1919.490 1800.000 ;
    END
  END commit_pc_o[2]
  PIN commit_pc_o[30]
    DIRECTION OUTPUT ;
    USE SIGNAL ;
    ANTENNADIFFAREA 0.891000 ;
    PORT
      LAYER met2 ;
        RECT 1887.010 1796.000 1887.290 1800.000 ;
    END
  END commit_pc_o[30]
  PIN commit_pc_o[31]
    DIRECTION OUTPUT ;
    USE SIGNAL ;
    ANTENNADIFFAREA 0.891000 ;
    PORT
      LAYER met2 ;
        RECT 1874.130 1796.000 1874.410 1800.000 ;
    END
  END commit_pc_o[31]
  PIN commit_pc_o[3]
    DIRECTION OUTPUT ;
    USE SIGNAL ;
    ANTENNADIFFAREA 0.891000 ;
    PORT
      LAYER met2 ;
        RECT 1915.990 1796.000 1916.270 1800.000 ;
    END
  END commit_pc_o[3]
  PIN commit_pc_o[4]
    DIRECTION OUTPUT ;
    USE SIGNAL ;
    ANTENNADIFFAREA 0.891000 ;
    PORT
      LAYER met2 ;
        RECT 2115.630 1796.000 2115.910 1800.000 ;
    END
  END commit_pc_o[4]
  PIN commit_pc_o[5]
    DIRECTION OUTPUT ;
    USE SIGNAL ;
    ANTENNADIFFAREA 0.891000 ;
    PORT
      LAYER met2 ;
        RECT 2102.750 1796.000 2103.030 1800.000 ;
    END
  END commit_pc_o[5]
  PIN commit_pc_o[6]
    DIRECTION OUTPUT ;
    USE SIGNAL ;
    ANTENNADIFFAREA 0.891000 ;
    PORT
      LAYER met2 ;
        RECT 1903.110 1796.000 1903.390 1800.000 ;
    END
  END commit_pc_o[6]
  PIN commit_pc_o[7]
    DIRECTION OUTPUT ;
    USE SIGNAL ;
    ANTENNADIFFAREA 0.891000 ;
    PORT
      LAYER met2 ;
        RECT 1867.690 1796.000 1867.970 1800.000 ;
    END
  END commit_pc_o[7]
  PIN commit_pc_o[8]
    DIRECTION OUTPUT ;
    USE SIGNAL ;
    ANTENNADIFFAREA 0.891000 ;
    PORT
      LAYER met2 ;
        RECT 1854.810 1796.000 1855.090 1800.000 ;
    END
  END commit_pc_o[8]
  PIN commit_pc_o[9]
    DIRECTION OUTPUT ;
    USE SIGNAL ;
    ANTENNADIFFAREA 0.891000 ;
    PORT
      LAYER met2 ;
        RECT 1858.030 1796.000 1858.310 1800.000 ;
    END
  END commit_pc_o[9]
  PIN commit_valid_o
    DIRECTION OUTPUT ;
    USE SIGNAL ;
    ANTENNADIFFAREA 0.891000 ;
    PORT
      LAYER met2 ;
        RECT 2015.810 1796.000 2016.090 1800.000 ;
    END
  END commit_valid_o
  PIN debug_branch_taken_o
    DIRECTION OUTPUT ;
    USE SIGNAL ;
    PORT
      LAYER met2 ;
        RECT 2891.650 1796.000 2891.930 1800.000 ;
    END
  END debug_branch_taken_o
  PIN debug_ebreak_o
    DIRECTION OUTPUT ;
    USE SIGNAL ;
    ANTENNADIFFAREA 0.891000 ;
    PORT
      LAYER met2 ;
        RECT 1738.890 1796.000 1739.170 1800.000 ;
    END
  END debug_ebreak_o
  PIN debug_pc_src_o
    DIRECTION OUTPUT ;
    USE SIGNAL ;
    ANTENNADIFFAREA 0.891000 ;
    PORT
      LAYER met2 ;
        RECT 1329.950 1796.000 1330.230 1800.000 ;
    END
  END debug_pc_src_o
  PIN debug_rs1_data_o[0]
    DIRECTION OUTPUT ;
    USE SIGNAL ;
    PORT
      LAYER met2 ;
        RECT 2611.510 1796.000 2611.790 1800.000 ;
    END
  END debug_rs1_data_o[0]
  PIN debug_rs1_data_o[10]
    DIRECTION OUTPUT ;
    USE SIGNAL ;
    PORT
      LAYER met2 ;
        RECT 2775.730 1796.000 2776.010 1800.000 ;
    END
  END debug_rs1_data_o[10]
  PIN debug_rs1_data_o[11]
    DIRECTION OUTPUT ;
    USE SIGNAL ;
    PORT
      LAYER met2 ;
        RECT 2968.930 1796.000 2969.210 1800.000 ;
    END
  END debug_rs1_data_o[11]
  PIN debug_rs1_data_o[12]
    DIRECTION OUTPUT ;
    USE SIGNAL ;
    PORT
      LAYER met3 ;
        RECT 3596.000 1207.040 3600.000 1207.640 ;
    END
  END debug_rs1_data_o[12]
  PIN debug_rs1_data_o[13]
    DIRECTION OUTPUT ;
    USE SIGNAL ;
    PORT
      LAYER met2 ;
        RECT 3046.210 1796.000 3046.490 1800.000 ;
    END
  END debug_rs1_data_o[13]
  PIN debug_rs1_data_o[14]
    DIRECTION OUTPUT ;
    USE SIGNAL ;
    PORT
      LAYER met2 ;
        RECT 3236.190 1796.000 3236.470 1800.000 ;
    END
  END debug_rs1_data_o[14]
  PIN debug_rs1_data_o[15]
    DIRECTION OUTPUT ;
    USE SIGNAL ;
    PORT
      LAYER met2 ;
        RECT 3406.850 1796.000 3407.130 1800.000 ;
    END
  END debug_rs1_data_o[15]
  PIN debug_rs1_data_o[16]
    DIRECTION OUTPUT ;
    USE SIGNAL ;
    PORT
      LAYER met3 ;
        RECT 3596.000 1754.440 3600.000 1755.040 ;
    END
  END debug_rs1_data_o[16]
  PIN debug_rs1_data_o[17]
    DIRECTION OUTPUT ;
    USE SIGNAL ;
    PORT
      LAYER met2 ;
        RECT 3175.010 1796.000 3175.290 1800.000 ;
    END
  END debug_rs1_data_o[17]
  PIN debug_rs1_data_o[18]
    DIRECTION OUTPUT ;
    USE SIGNAL ;
    PORT
      LAYER met2 ;
        RECT 3149.250 1796.000 3149.530 1800.000 ;
    END
  END debug_rs1_data_o[18]
  PIN debug_rs1_data_o[19]
    DIRECTION OUTPUT ;
    USE SIGNAL ;
    PORT
      LAYER met3 ;
        RECT 3596.000 1706.840 3600.000 1707.440 ;
    END
  END debug_rs1_data_o[19]
  PIN debug_rs1_data_o[1]
    DIRECTION OUTPUT ;
    USE SIGNAL ;
    PORT
      LAYER met2 ;
        RECT 2939.950 1796.000 2940.230 1800.000 ;
    END
  END debug_rs1_data_o[1]
  PIN debug_rs1_data_o[20]
    DIRECTION OUTPUT ;
    USE SIGNAL ;
    PORT
      LAYER met2 ;
        RECT 2814.370 1796.000 2814.650 1800.000 ;
    END
  END debug_rs1_data_o[20]
  PIN debug_rs1_data_o[21]
    DIRECTION OUTPUT ;
    USE SIGNAL ;
    PORT
      LAYER met2 ;
        RECT 3104.170 1796.000 3104.450 1800.000 ;
    END
  END debug_rs1_data_o[21]
  PIN debug_rs1_data_o[22]
    DIRECTION OUTPUT ;
    USE SIGNAL ;
    PORT
      LAYER met2 ;
        RECT 3471.250 1796.000 3471.530 1800.000 ;
    END
  END debug_rs1_data_o[22]
  PIN debug_rs1_data_o[23]
    DIRECTION OUTPUT ;
    USE SIGNAL ;
    PORT
      LAYER met2 ;
        RECT 2550.330 1796.000 2550.610 1800.000 ;
    END
  END debug_rs1_data_o[23]
  PIN debug_rs1_data_o[24]
    DIRECTION OUTPUT ;
    USE SIGNAL ;
    PORT
      LAYER met2 ;
        RECT 2865.890 1796.000 2866.170 1800.000 ;
    END
  END debug_rs1_data_o[24]
  PIN debug_rs1_data_o[25]
    DIRECTION OUTPUT ;
    USE SIGNAL ;
    PORT
      LAYER met2 ;
        RECT 2440.850 1796.000 2441.130 1800.000 ;
    END
  END debug_rs1_data_o[25]
  PIN debug_rs1_data_o[26]
    DIRECTION OUTPUT ;
    USE SIGNAL ;
    PORT
      LAYER met2 ;
        RECT 3100.950 1796.000 3101.230 1800.000 ;
    END
  END debug_rs1_data_o[26]
  PIN debug_rs1_data_o[27]
    DIRECTION OUTPUT ;
    USE SIGNAL ;
    PORT
      LAYER met2 ;
        RECT 2972.150 1796.000 2972.430 1800.000 ;
    END
  END debug_rs1_data_o[27]
  PIN debug_rs1_data_o[28]
    DIRECTION OUTPUT ;
    USE SIGNAL ;
    PORT
      LAYER met3 ;
        RECT 3596.000 1431.440 3600.000 1432.040 ;
    END
  END debug_rs1_data_o[28]
  PIN debug_rs1_data_o[29]
    DIRECTION OUTPUT ;
    USE SIGNAL ;
    PORT
      LAYER met2 ;
        RECT 2685.570 1796.000 2685.850 1800.000 ;
    END
  END debug_rs1_data_o[29]
  PIN debug_rs1_data_o[2]
    DIRECTION OUTPUT ;
    USE SIGNAL ;
    PORT
      LAYER met2 ;
        RECT 3381.090 1796.000 3381.370 1800.000 ;
    END
  END debug_rs1_data_o[2]
  PIN debug_rs1_data_o[30]
    DIRECTION OUTPUT ;
    USE SIGNAL ;
    PORT
      LAYER met2 ;
        RECT 2914.190 1796.000 2914.470 1800.000 ;
    END
  END debug_rs1_data_o[30]
  PIN debug_rs1_data_o[31]
    DIRECTION OUTPUT ;
    USE SIGNAL ;
    PORT
      LAYER met2 ;
        RECT 2840.130 1796.000 2840.410 1800.000 ;
    END
  END debug_rs1_data_o[31]
  PIN debug_rs1_data_o[3]
    DIRECTION OUTPUT ;
    USE SIGNAL ;
    PORT
      LAYER met2 ;
        RECT 3242.630 1796.000 3242.910 1800.000 ;
    END
  END debug_rs1_data_o[3]
  PIN debug_rs1_data_o[4]
    DIRECTION OUTPUT ;
    USE SIGNAL ;
    PORT
      LAYER met2 ;
        RECT 2563.210 1796.000 2563.490 1800.000 ;
    END
  END debug_rs1_data_o[4]
  PIN debug_rs1_data_o[5]
    DIRECTION OUTPUT ;
    USE SIGNAL ;
    PORT
      LAYER met2 ;
        RECT 2920.630 1796.000 2920.910 1800.000 ;
    END
  END debug_rs1_data_o[5]
  PIN debug_rs1_data_o[6]
    DIRECTION OUTPUT ;
    USE SIGNAL ;
    PORT
      LAYER met3 ;
        RECT 3596.000 1672.840 3600.000 1673.440 ;
    END
  END debug_rs1_data_o[6]
  PIN debug_rs1_data_o[7]
    DIRECTION OUTPUT ;
    USE SIGNAL ;
    PORT
      LAYER met2 ;
        RECT 3194.330 1796.000 3194.610 1800.000 ;
    END
  END debug_rs1_data_o[7]
  PIN debug_rs1_data_o[8]
    DIRECTION OUTPUT ;
    USE SIGNAL ;
    PORT
      LAYER met3 ;
        RECT 3596.000 1686.440 3600.000 1687.040 ;
    END
  END debug_rs1_data_o[8]
  PIN debug_rs1_data_o[9]
    DIRECTION OUTPUT ;
    USE SIGNAL ;
    PORT
      LAYER met3 ;
        RECT 3596.000 1516.440 3600.000 1517.040 ;
    END
  END debug_rs1_data_o[9]
  PIN debug_rs2_data_o[0]
    DIRECTION OUTPUT ;
    USE SIGNAL ;
    PORT
      LAYER met3 ;
        RECT 3596.000 1761.240 3600.000 1761.840 ;
    END
  END debug_rs2_data_o[0]
  PIN debug_rs2_data_o[10]
    DIRECTION OUTPUT ;
    USE SIGNAL ;
    PORT
      LAYER met3 ;
        RECT 3596.000 1360.040 3600.000 1360.640 ;
    END
  END debug_rs2_data_o[10]
  PIN debug_rs2_data_o[11]
    DIRECTION OUTPUT ;
    USE SIGNAL ;
    PORT
      LAYER met2 ;
        RECT 2637.270 1796.000 2637.550 1800.000 ;
    END
  END debug_rs2_data_o[11]
  PIN debug_rs2_data_o[12]
    DIRECTION OUTPUT ;
    USE SIGNAL ;
    PORT
      LAYER met2 ;
        RECT 2170.370 1796.000 2170.650 1800.000 ;
    END
  END debug_rs2_data_o[12]
  PIN debug_rs2_data_o[13]
    DIRECTION OUTPUT ;
    USE SIGNAL ;
    PORT
      LAYER met2 ;
        RECT 3290.930 1796.000 3291.210 1800.000 ;
    END
  END debug_rs2_data_o[13]
  PIN debug_rs2_data_o[14]
    DIRECTION OUTPUT ;
    USE SIGNAL ;
    PORT
      LAYER met2 ;
        RECT 2904.530 1796.000 2904.810 1800.000 ;
    END
  END debug_rs2_data_o[14]
  PIN debug_rs2_data_o[15]
    DIRECTION OUTPUT ;
    USE SIGNAL ;
    PORT
      LAYER met2 ;
        RECT 2688.790 1796.000 2689.070 1800.000 ;
    END
  END debug_rs2_data_o[15]
  PIN debug_rs2_data_o[16]
    DIRECTION OUTPUT ;
    USE SIGNAL ;
    PORT
      LAYER met2 ;
        RECT 3158.910 1796.000 3159.190 1800.000 ;
    END
  END debug_rs2_data_o[16]
  PIN debug_rs2_data_o[17]
    DIRECTION OUTPUT ;
    USE SIGNAL ;
    PORT
      LAYER met2 ;
        RECT 2601.850 1796.000 2602.130 1800.000 ;
    END
  END debug_rs2_data_o[17]
  PIN debug_rs2_data_o[18]
    DIRECTION OUTPUT ;
    USE SIGNAL ;
    PORT
      LAYER met2 ;
        RECT 3055.870 1796.000 3056.150 1800.000 ;
    END
  END debug_rs2_data_o[18]
  PIN debug_rs2_data_o[19]
    DIRECTION OUTPUT ;
    USE SIGNAL ;
    PORT
      LAYER met2 ;
        RECT 3010.790 1796.000 3011.070 1800.000 ;
    END
  END debug_rs2_data_o[19]
  PIN debug_rs2_data_o[1]
    DIRECTION OUTPUT ;
    USE SIGNAL ;
    PORT
      LAYER met2 ;
        RECT 2666.250 1796.000 2666.530 1800.000 ;
    END
  END debug_rs2_data_o[1]
  PIN debug_rs2_data_o[20]
    DIRECTION OUTPUT ;
    USE SIGNAL ;
    PORT
      LAYER met2 ;
        RECT 2782.170 1796.000 2782.450 1800.000 ;
    END
  END debug_rs2_data_o[20]
  PIN debug_rs2_data_o[21]
    DIRECTION OUTPUT ;
    USE SIGNAL ;
    PORT
      LAYER met2 ;
        RECT 2447.290 1796.000 2447.570 1800.000 ;
    END
  END debug_rs2_data_o[21]
  PIN debug_rs2_data_o[22]
    DIRECTION OUTPUT ;
    USE SIGNAL ;
    PORT
      LAYER met2 ;
        RECT 2778.950 1796.000 2779.230 1800.000 ;
    END
  END debug_rs2_data_o[22]
  PIN debug_rs2_data_o[23]
    DIRECTION OUTPUT ;
    USE SIGNAL ;
    PORT
      LAYER met2 ;
        RECT 3258.730 1796.000 3259.010 1800.000 ;
    END
  END debug_rs2_data_o[23]
  PIN debug_rs2_data_o[24]
    DIRECTION OUTPUT ;
    USE SIGNAL ;
    PORT
      LAYER met2 ;
        RECT 3107.390 1796.000 3107.670 1800.000 ;
    END
  END debug_rs2_data_o[24]
  PIN debug_rs2_data_o[25]
    DIRECTION OUTPUT ;
    USE SIGNAL ;
    PORT
      LAYER met2 ;
        RECT 2444.070 1796.000 2444.350 1800.000 ;
    END
  END debug_rs2_data_o[25]
  PIN debug_rs2_data_o[26]
    DIRECTION OUTPUT ;
    USE SIGNAL ;
    PORT
      LAYER met3 ;
        RECT 3596.000 1404.240 3600.000 1404.840 ;
    END
  END debug_rs2_data_o[26]
  PIN debug_rs2_data_o[27]
    DIRECTION OUTPUT ;
    USE SIGNAL ;
    PORT
      LAYER met2 ;
        RECT 3207.210 1796.000 3207.490 1800.000 ;
    END
  END debug_rs2_data_o[27]
  PIN debug_rs2_data_o[28]
    DIRECTION OUTPUT ;
    USE SIGNAL ;
    PORT
      LAYER met2 ;
        RECT 2099.530 1796.000 2099.810 1800.000 ;
    END
  END debug_rs2_data_o[28]
  PIN debug_rs2_data_o[29]
    DIRECTION OUTPUT ;
    USE SIGNAL ;
    PORT
      LAYER met2 ;
        RECT 3249.070 1796.000 3249.350 1800.000 ;
    END
  END debug_rs2_data_o[29]
  PIN debug_rs2_data_o[2]
    DIRECTION OUTPUT ;
    USE SIGNAL ;
    PORT
      LAYER met3 ;
        RECT 3596.000 1594.640 3600.000 1595.240 ;
    END
  END debug_rs2_data_o[2]
  PIN debug_rs2_data_o[30]
    DIRECTION OUTPUT ;
    USE SIGNAL ;
    PORT
      LAYER met3 ;
        RECT 3596.000 1258.040 3600.000 1258.640 ;
    END
  END debug_rs2_data_o[30]
  PIN debug_rs2_data_o[31]
    DIRECTION OUTPUT ;
    USE SIGNAL ;
    PORT
      LAYER met3 ;
        RECT 3596.000 1570.840 3600.000 1571.440 ;
    END
  END debug_rs2_data_o[31]
  PIN debug_rs2_data_o[3]
    DIRECTION OUTPUT ;
    USE SIGNAL ;
    PORT
      LAYER met2 ;
        RECT 2965.710 1796.000 2965.990 1800.000 ;
    END
  END debug_rs2_data_o[3]
  PIN debug_rs2_data_o[4]
    DIRECTION OUTPUT ;
    USE SIGNAL ;
    PORT
      LAYER met2 ;
        RECT 2695.230 1796.000 2695.510 1800.000 ;
    END
  END debug_rs2_data_o[4]
  PIN debug_rs2_data_o[5]
    DIRECTION OUTPUT ;
    USE SIGNAL ;
    PORT
      LAYER met2 ;
        RECT 2225.110 1796.000 2225.390 1800.000 ;
    END
  END debug_rs2_data_o[5]
  PIN debug_rs2_data_o[6]
    DIRECTION OUTPUT ;
    USE SIGNAL ;
    PORT
      LAYER met3 ;
        RECT 3596.000 1768.040 3600.000 1768.640 ;
    END
  END debug_rs2_data_o[6]
  PIN debug_rs2_data_o[7]
    DIRECTION OUTPUT ;
    USE SIGNAL ;
    PORT
      LAYER met2 ;
        RECT 3239.410 1796.000 3239.690 1800.000 ;
    END
  END debug_rs2_data_o[7]
  PIN debug_rs2_data_o[8]
    DIRECTION OUTPUT ;
    USE SIGNAL ;
    PORT
      LAYER met2 ;
        RECT 2630.830 1796.000 2631.110 1800.000 ;
    END
  END debug_rs2_data_o[8]
  PIN debug_rs2_data_o[9]
    DIRECTION OUTPUT ;
    USE SIGNAL ;
    PORT
      LAYER met2 ;
        RECT 3007.570 1796.000 3007.850 1800.000 ;
    END
  END debug_rs2_data_o[9]
  PIN debug_state_o[0]
    DIRECTION OUTPUT ;
    USE SIGNAL ;
    PORT
      LAYER met2 ;
        RECT 3374.650 1796.000 3374.930 1800.000 ;
    END
  END debug_state_o[0]
  PIN debug_state_o[1]
    DIRECTION OUTPUT ;
    USE SIGNAL ;
    PORT
      LAYER met2 ;
        RECT 3245.850 1796.000 3246.130 1800.000 ;
    END
  END debug_state_o[1]
  PIN debug_state_o[2]
    DIRECTION OUTPUT ;
    USE SIGNAL ;
    PORT
      LAYER met2 ;
        RECT 3075.190 1796.000 3075.470 1800.000 ;
    END
  END debug_state_o[2]
  PIN debug_state_o[3]
    DIRECTION OUTPUT ;
    USE SIGNAL ;
    PORT
      LAYER met2 ;
        RECT 3033.330 1796.000 3033.610 1800.000 ;
    END
  END debug_state_o[3]
  PIN debug_take_branch_jump_o
    DIRECTION OUTPUT ;
    USE SIGNAL ;
    ANTENNADIFFAREA 0.891000 ;
    PORT
      LAYER met2 ;
        RECT 1333.170 1796.000 1333.450 1800.000 ;
    END
  END debug_take_branch_jump_o
  PIN ext_irq_i
    DIRECTION INPUT ;
    USE SIGNAL ;
    ANTENNAGATEAREA 0.647700 ;
    ANTENNADIFFAREA 0.434700 ;
    PORT
      LAYER met2 ;
        RECT 1664.830 1796.000 1665.110 1800.000 ;
    END
  END ext_irq_i
  PIN rst_n_i
    DIRECTION INPUT ;
    USE SIGNAL ;
    ANTENNAGATEAREA 1.424700 ;
    ANTENNADIFFAREA 0.434700 ;
    PORT
      LAYER met2 ;
        RECT 2289.510 1796.000 2289.790 1800.000 ;
    END
  END rst_n_i
  PIN timer_irq_i
    DIRECTION INPUT ;
    USE SIGNAL ;
    ANTENNAGATEAREA 0.647700 ;
    ANTENNADIFFAREA 0.434700 ;
    PORT
      LAYER met2 ;
        RECT 1651.950 1796.000 1652.230 1800.000 ;
    END
  END timer_irq_i
  PIN trap_cause_o[0]
    DIRECTION OUTPUT ;
    USE SIGNAL ;
    ANTENNADIFFAREA 0.891000 ;
    PORT
      LAYER met2 ;
        RECT 1822.610 1796.000 1822.890 1800.000 ;
    END
  END trap_cause_o[0]
  PIN trap_cause_o[1]
    DIRECTION OUTPUT ;
    USE SIGNAL ;
    ANTENNADIFFAREA 0.891000 ;
    PORT
      LAYER met2 ;
        RECT 1812.950 1796.000 1813.230 1800.000 ;
    END
  END trap_cause_o[1]
  PIN trap_cause_o[2]
    DIRECTION OUTPUT ;
    USE SIGNAL ;
    ANTENNADIFFAREA 0.891000 ;
    PORT
      LAYER met2 ;
        RECT 1819.390 1796.000 1819.670 1800.000 ;
    END
  END trap_cause_o[2]
  PIN trap_cause_o[3]
    DIRECTION OUTPUT ;
    USE SIGNAL ;
    ANTENNADIFFAREA 0.891000 ;
    PORT
      LAYER met2 ;
        RECT 1816.170 1796.000 1816.450 1800.000 ;
    END
  END trap_cause_o[3]
  PIN trap_taken_o
    DIRECTION OUTPUT ;
    USE SIGNAL ;
    ANTENNADIFFAREA 0.891000 ;
    PORT
      LAYER met2 ;
        RECT 1796.850 1796.000 1797.130 1800.000 ;
    END
  END trap_taken_o
  OBS
      LAYER nwell ;
        RECT 20.050 21.675 3579.910 1778.965 ;
      LAYER li1 ;
        RECT 20.240 21.675 3579.720 1778.965 ;
      LAYER met1 ;
        RECT 6.510 0.040 3588.390 1785.980 ;
      LAYER met2 ;
        RECT 6.530 1795.720 775.830 1796.290 ;
        RECT 776.670 1795.720 791.930 1796.290 ;
        RECT 792.770 1795.720 820.910 1796.290 ;
        RECT 821.750 1795.720 824.130 1796.290 ;
        RECT 824.970 1795.720 827.350 1796.290 ;
        RECT 828.190 1795.720 830.570 1796.290 ;
        RECT 831.410 1795.720 833.790 1796.290 ;
        RECT 834.630 1795.720 837.010 1796.290 ;
        RECT 837.850 1795.720 1284.590 1796.290 ;
        RECT 1285.430 1795.720 1287.810 1796.290 ;
        RECT 1288.650 1795.720 1329.670 1796.290 ;
        RECT 1330.510 1795.720 1332.890 1796.290 ;
        RECT 1333.730 1795.720 1336.110 1796.290 ;
        RECT 1336.950 1795.720 1339.330 1796.290 ;
        RECT 1340.170 1795.720 1497.110 1796.290 ;
        RECT 1497.950 1795.720 1558.290 1796.290 ;
        RECT 1559.130 1795.720 1571.170 1796.290 ;
        RECT 1572.010 1795.720 1577.610 1796.290 ;
        RECT 1578.450 1795.720 1596.930 1796.290 ;
        RECT 1597.770 1795.720 1606.590 1796.290 ;
        RECT 1607.430 1795.720 1609.810 1796.290 ;
        RECT 1610.650 1795.720 1629.130 1796.290 ;
        RECT 1629.970 1795.720 1638.790 1796.290 ;
        RECT 1639.630 1795.720 1642.010 1796.290 ;
        RECT 1642.850 1795.720 1648.450 1796.290 ;
        RECT 1649.290 1795.720 1651.670 1796.290 ;
        RECT 1652.510 1795.720 1654.890 1796.290 ;
        RECT 1655.730 1795.720 1658.110 1796.290 ;
        RECT 1658.950 1795.720 1661.330 1796.290 ;
        RECT 1662.170 1795.720 1664.550 1796.290 ;
        RECT 1665.390 1795.720 1667.770 1796.290 ;
        RECT 1668.610 1795.720 1670.990 1796.290 ;
        RECT 1671.830 1795.720 1674.210 1796.290 ;
        RECT 1675.050 1795.720 1677.430 1796.290 ;
        RECT 1678.270 1795.720 1680.650 1796.290 ;
        RECT 1681.490 1795.720 1683.870 1796.290 ;
        RECT 1684.710 1795.720 1687.090 1796.290 ;
        RECT 1687.930 1795.720 1690.310 1796.290 ;
        RECT 1691.150 1795.720 1693.530 1796.290 ;
        RECT 1694.370 1795.720 1696.750 1796.290 ;
        RECT 1697.590 1795.720 1699.970 1796.290 ;
        RECT 1700.810 1795.720 1703.190 1796.290 ;
        RECT 1704.030 1795.720 1706.410 1796.290 ;
        RECT 1707.250 1795.720 1709.630 1796.290 ;
        RECT 1710.470 1795.720 1712.850 1796.290 ;
        RECT 1713.690 1795.720 1716.070 1796.290 ;
        RECT 1716.910 1795.720 1719.290 1796.290 ;
        RECT 1720.130 1795.720 1722.510 1796.290 ;
        RECT 1723.350 1795.720 1725.730 1796.290 ;
        RECT 1726.570 1795.720 1728.950 1796.290 ;
        RECT 1729.790 1795.720 1732.170 1796.290 ;
        RECT 1733.010 1795.720 1735.390 1796.290 ;
        RECT 1736.230 1795.720 1738.610 1796.290 ;
        RECT 1739.450 1795.720 1741.830 1796.290 ;
        RECT 1742.670 1795.720 1745.050 1796.290 ;
        RECT 1745.890 1795.720 1748.270 1796.290 ;
        RECT 1749.110 1795.720 1751.490 1796.290 ;
        RECT 1752.330 1795.720 1754.710 1796.290 ;
        RECT 1755.550 1795.720 1757.930 1796.290 ;
        RECT 1758.770 1795.720 1761.150 1796.290 ;
        RECT 1761.990 1795.720 1764.370 1796.290 ;
        RECT 1765.210 1795.720 1767.590 1796.290 ;
        RECT 1768.430 1795.720 1770.810 1796.290 ;
        RECT 1771.650 1795.720 1774.030 1796.290 ;
        RECT 1774.870 1795.720 1777.250 1796.290 ;
        RECT 1778.090 1795.720 1780.470 1796.290 ;
        RECT 1781.310 1795.720 1783.690 1796.290 ;
        RECT 1784.530 1795.720 1786.910 1796.290 ;
        RECT 1787.750 1795.720 1790.130 1796.290 ;
        RECT 1790.970 1795.720 1793.350 1796.290 ;
        RECT 1794.190 1795.720 1796.570 1796.290 ;
        RECT 1797.410 1795.720 1799.790 1796.290 ;
        RECT 1800.630 1795.720 1803.010 1796.290 ;
        RECT 1803.850 1795.720 1806.230 1796.290 ;
        RECT 1807.070 1795.720 1809.450 1796.290 ;
        RECT 1810.290 1795.720 1812.670 1796.290 ;
        RECT 1813.510 1795.720 1815.890 1796.290 ;
        RECT 1816.730 1795.720 1819.110 1796.290 ;
        RECT 1819.950 1795.720 1822.330 1796.290 ;
        RECT 1823.170 1795.720 1825.550 1796.290 ;
        RECT 1826.390 1795.720 1828.770 1796.290 ;
        RECT 1829.610 1795.720 1831.990 1796.290 ;
        RECT 1832.830 1795.720 1835.210 1796.290 ;
        RECT 1836.050 1795.720 1838.430 1796.290 ;
        RECT 1839.270 1795.720 1841.650 1796.290 ;
        RECT 1842.490 1795.720 1844.870 1796.290 ;
        RECT 1845.710 1795.720 1848.090 1796.290 ;
        RECT 1848.930 1795.720 1851.310 1796.290 ;
        RECT 1852.150 1795.720 1854.530 1796.290 ;
        RECT 1855.370 1795.720 1857.750 1796.290 ;
        RECT 1858.590 1795.720 1860.970 1796.290 ;
        RECT 1861.810 1795.720 1864.190 1796.290 ;
        RECT 1865.030 1795.720 1867.410 1796.290 ;
        RECT 1868.250 1795.720 1870.630 1796.290 ;
        RECT 1871.470 1795.720 1873.850 1796.290 ;
        RECT 1874.690 1795.720 1877.070 1796.290 ;
        RECT 1877.910 1795.720 1880.290 1796.290 ;
        RECT 1881.130 1795.720 1883.510 1796.290 ;
        RECT 1884.350 1795.720 1886.730 1796.290 ;
        RECT 1887.570 1795.720 1889.950 1796.290 ;
        RECT 1890.790 1795.720 1893.170 1796.290 ;
        RECT 1894.010 1795.720 1896.390 1796.290 ;
        RECT 1897.230 1795.720 1899.610 1796.290 ;
        RECT 1900.450 1795.720 1902.830 1796.290 ;
        RECT 1903.670 1795.720 1906.050 1796.290 ;
        RECT 1906.890 1795.720 1909.270 1796.290 ;
        RECT 1910.110 1795.720 1912.490 1796.290 ;
        RECT 1913.330 1795.720 1915.710 1796.290 ;
        RECT 1916.550 1795.720 1918.930 1796.290 ;
        RECT 1919.770 1795.720 1922.150 1796.290 ;
        RECT 1922.990 1795.720 1925.370 1796.290 ;
        RECT 1926.210 1795.720 1928.590 1796.290 ;
        RECT 1929.430 1795.720 1931.810 1796.290 ;
        RECT 1932.650 1795.720 1935.030 1796.290 ;
        RECT 1935.870 1795.720 1938.250 1796.290 ;
        RECT 1939.090 1795.720 1941.470 1796.290 ;
        RECT 1942.310 1795.720 1944.690 1796.290 ;
        RECT 1945.530 1795.720 1947.910 1796.290 ;
        RECT 1948.750 1795.720 1951.130 1796.290 ;
        RECT 1951.970 1795.720 1954.350 1796.290 ;
        RECT 1955.190 1795.720 1957.570 1796.290 ;
        RECT 1958.410 1795.720 1960.790 1796.290 ;
        RECT 1961.630 1795.720 1964.010 1796.290 ;
        RECT 1964.850 1795.720 1967.230 1796.290 ;
        RECT 1968.070 1795.720 1970.450 1796.290 ;
        RECT 1971.290 1795.720 1973.670 1796.290 ;
        RECT 1974.510 1795.720 1976.890 1796.290 ;
        RECT 1977.730 1795.720 1980.110 1796.290 ;
        RECT 1980.950 1795.720 1983.330 1796.290 ;
        RECT 1984.170 1795.720 1986.550 1796.290 ;
        RECT 1987.390 1795.720 1989.770 1796.290 ;
        RECT 1990.610 1795.720 1992.990 1796.290 ;
        RECT 1993.830 1795.720 1996.210 1796.290 ;
        RECT 1997.050 1795.720 1999.430 1796.290 ;
        RECT 2000.270 1795.720 2002.650 1796.290 ;
        RECT 2003.490 1795.720 2005.870 1796.290 ;
        RECT 2006.710 1795.720 2009.090 1796.290 ;
        RECT 2009.930 1795.720 2012.310 1796.290 ;
        RECT 2013.150 1795.720 2015.530 1796.290 ;
        RECT 2016.370 1795.720 2018.750 1796.290 ;
        RECT 2019.590 1795.720 2021.970 1796.290 ;
        RECT 2022.810 1795.720 2025.190 1796.290 ;
        RECT 2026.030 1795.720 2028.410 1796.290 ;
        RECT 2029.250 1795.720 2031.630 1796.290 ;
        RECT 2032.470 1795.720 2034.850 1796.290 ;
        RECT 2035.690 1795.720 2038.070 1796.290 ;
        RECT 2038.910 1795.720 2041.290 1796.290 ;
        RECT 2042.130 1795.720 2044.510 1796.290 ;
        RECT 2045.350 1795.720 2047.730 1796.290 ;
        RECT 2048.570 1795.720 2050.950 1796.290 ;
        RECT 2051.790 1795.720 2054.170 1796.290 ;
        RECT 2055.010 1795.720 2057.390 1796.290 ;
        RECT 2058.230 1795.720 2060.610 1796.290 ;
        RECT 2061.450 1795.720 2063.830 1796.290 ;
        RECT 2064.670 1795.720 2067.050 1796.290 ;
        RECT 2067.890 1795.720 2070.270 1796.290 ;
        RECT 2071.110 1795.720 2073.490 1796.290 ;
        RECT 2074.330 1795.720 2076.710 1796.290 ;
        RECT 2077.550 1795.720 2079.930 1796.290 ;
        RECT 2080.770 1795.720 2083.150 1796.290 ;
        RECT 2083.990 1795.720 2086.370 1796.290 ;
        RECT 2087.210 1795.720 2089.590 1796.290 ;
        RECT 2090.430 1795.720 2092.810 1796.290 ;
        RECT 2093.650 1795.720 2096.030 1796.290 ;
        RECT 2096.870 1795.720 2099.250 1796.290 ;
        RECT 2100.090 1795.720 2102.470 1796.290 ;
        RECT 2103.310 1795.720 2105.690 1796.290 ;
        RECT 2106.530 1795.720 2108.910 1796.290 ;
        RECT 2109.750 1795.720 2112.130 1796.290 ;
        RECT 2112.970 1795.720 2115.350 1796.290 ;
        RECT 2116.190 1795.720 2118.570 1796.290 ;
        RECT 2119.410 1795.720 2121.790 1796.290 ;
        RECT 2122.630 1795.720 2125.010 1796.290 ;
        RECT 2125.850 1795.720 2128.230 1796.290 ;
        RECT 2129.070 1795.720 2170.090 1796.290 ;
        RECT 2170.930 1795.720 2224.830 1796.290 ;
        RECT 2225.670 1795.720 2257.030 1796.290 ;
        RECT 2257.870 1795.720 2289.230 1796.290 ;
        RECT 2290.070 1795.720 2292.450 1796.290 ;
        RECT 2293.290 1795.720 2295.670 1796.290 ;
        RECT 2296.510 1795.720 2298.890 1796.290 ;
        RECT 2299.730 1795.720 2302.110 1796.290 ;
        RECT 2302.950 1795.720 2305.330 1796.290 ;
        RECT 2306.170 1795.720 2308.550 1796.290 ;
        RECT 2309.390 1795.720 2376.170 1796.290 ;
        RECT 2377.010 1795.720 2408.370 1796.290 ;
        RECT 2409.210 1795.720 2440.570 1796.290 ;
        RECT 2441.410 1795.720 2443.790 1796.290 ;
        RECT 2444.630 1795.720 2447.010 1796.290 ;
        RECT 2447.850 1795.720 2550.050 1796.290 ;
        RECT 2550.890 1795.720 2562.930 1796.290 ;
        RECT 2563.770 1795.720 2566.150 1796.290 ;
        RECT 2566.990 1795.720 2601.570 1796.290 ;
        RECT 2602.410 1795.720 2608.010 1796.290 ;
        RECT 2608.850 1795.720 2611.230 1796.290 ;
        RECT 2612.070 1795.720 2630.550 1796.290 ;
        RECT 2631.390 1795.720 2636.990 1796.290 ;
        RECT 2637.830 1795.720 2665.970 1796.290 ;
        RECT 2666.810 1795.720 2685.290 1796.290 ;
        RECT 2686.130 1795.720 2688.510 1796.290 ;
        RECT 2689.350 1795.720 2694.950 1796.290 ;
        RECT 2695.790 1795.720 2775.450 1796.290 ;
        RECT 2776.290 1795.720 2778.670 1796.290 ;
        RECT 2779.510 1795.720 2781.890 1796.290 ;
        RECT 2782.730 1795.720 2814.090 1796.290 ;
        RECT 2814.930 1795.720 2839.850 1796.290 ;
        RECT 2840.690 1795.720 2865.610 1796.290 ;
        RECT 2866.450 1795.720 2881.710 1796.290 ;
        RECT 2882.550 1795.720 2888.150 1796.290 ;
        RECT 2888.990 1795.720 2891.370 1796.290 ;
        RECT 2892.210 1795.720 2904.250 1796.290 ;
        RECT 2905.090 1795.720 2913.910 1796.290 ;
        RECT 2914.750 1795.720 2920.350 1796.290 ;
        RECT 2921.190 1795.720 2939.670 1796.290 ;
        RECT 2940.510 1795.720 2965.430 1796.290 ;
        RECT 2966.270 1795.720 2968.650 1796.290 ;
        RECT 2969.490 1795.720 2971.870 1796.290 ;
        RECT 2972.710 1795.720 2997.630 1796.290 ;
        RECT 2998.470 1795.720 3004.070 1796.290 ;
        RECT 3004.910 1795.720 3007.290 1796.290 ;
        RECT 3008.130 1795.720 3010.510 1796.290 ;
        RECT 3011.350 1795.720 3033.050 1796.290 ;
        RECT 3033.890 1795.720 3045.930 1796.290 ;
        RECT 3046.770 1795.720 3055.590 1796.290 ;
        RECT 3056.430 1795.720 3074.910 1796.290 ;
        RECT 3075.750 1795.720 3078.130 1796.290 ;
        RECT 3078.970 1795.720 3100.670 1796.290 ;
        RECT 3101.510 1795.720 3103.890 1796.290 ;
        RECT 3104.730 1795.720 3107.110 1796.290 ;
        RECT 3107.950 1795.720 3132.870 1796.290 ;
        RECT 3133.710 1795.720 3136.090 1796.290 ;
        RECT 3136.930 1795.720 3148.970 1796.290 ;
        RECT 3149.810 1795.720 3158.630 1796.290 ;
        RECT 3159.470 1795.720 3161.850 1796.290 ;
        RECT 3162.690 1795.720 3174.730 1796.290 ;
        RECT 3175.570 1795.720 3187.610 1796.290 ;
        RECT 3188.450 1795.720 3194.050 1796.290 ;
        RECT 3194.890 1795.720 3206.930 1796.290 ;
        RECT 3207.770 1795.720 3235.910 1796.290 ;
        RECT 3236.750 1795.720 3239.130 1796.290 ;
        RECT 3239.970 1795.720 3242.350 1796.290 ;
        RECT 3243.190 1795.720 3245.570 1796.290 ;
        RECT 3246.410 1795.720 3248.790 1796.290 ;
        RECT 3249.630 1795.720 3258.450 1796.290 ;
        RECT 3259.290 1795.720 3290.650 1796.290 ;
        RECT 3291.490 1795.720 3313.190 1796.290 ;
        RECT 3314.030 1795.720 3329.290 1796.290 ;
        RECT 3330.130 1795.720 3355.050 1796.290 ;
        RECT 3355.890 1795.720 3371.150 1796.290 ;
        RECT 3371.990 1795.720 3374.370 1796.290 ;
        RECT 3375.210 1795.720 3377.590 1796.290 ;
        RECT 3378.430 1795.720 3380.810 1796.290 ;
        RECT 3381.650 1795.720 3406.570 1796.290 ;
        RECT 3407.410 1795.720 3467.750 1796.290 ;
        RECT 3468.590 1795.720 3470.970 1796.290 ;
        RECT 3471.810 1795.720 3588.370 1796.290 ;
        RECT 6.530 4.280 3588.370 1795.720 ;
        RECT 6.530 0.010 131.830 4.280 ;
        RECT 132.670 0.010 421.630 4.280 ;
        RECT 422.470 0.010 424.850 4.280 ;
        RECT 425.690 0.010 431.290 4.280 ;
        RECT 432.130 0.010 450.610 4.280 ;
        RECT 451.450 0.010 469.930 4.280 ;
        RECT 470.770 0.010 476.370 4.280 ;
        RECT 477.210 0.010 498.910 4.280 ;
        RECT 499.750 0.010 508.570 4.280 ;
        RECT 509.410 0.010 518.230 4.280 ;
        RECT 519.070 0.010 524.670 4.280 ;
        RECT 525.510 0.010 527.890 4.280 ;
        RECT 528.730 0.010 531.110 4.280 ;
        RECT 531.950 0.010 537.550 4.280 ;
        RECT 538.390 0.010 540.770 4.280 ;
        RECT 541.610 0.010 550.430 4.280 ;
        RECT 551.270 0.010 553.650 4.280 ;
        RECT 554.490 0.010 560.090 4.280 ;
        RECT 560.930 0.010 566.530 4.280 ;
        RECT 567.370 0.010 572.970 4.280 ;
        RECT 573.810 0.010 595.510 4.280 ;
        RECT 596.350 0.010 598.730 4.280 ;
        RECT 599.570 0.010 601.950 4.280 ;
        RECT 602.790 0.010 605.170 4.280 ;
        RECT 606.010 0.010 608.390 4.280 ;
        RECT 609.230 0.010 611.610 4.280 ;
        RECT 612.450 0.010 614.830 4.280 ;
        RECT 615.670 0.010 618.050 4.280 ;
        RECT 618.890 0.010 621.270 4.280 ;
        RECT 622.110 0.010 627.710 4.280 ;
        RECT 628.550 0.010 630.930 4.280 ;
        RECT 631.770 0.010 634.150 4.280 ;
        RECT 634.990 0.010 637.370 4.280 ;
        RECT 638.210 0.010 640.590 4.280 ;
        RECT 641.430 0.010 643.810 4.280 ;
        RECT 644.650 0.010 647.030 4.280 ;
        RECT 647.870 0.010 650.250 4.280 ;
        RECT 651.090 0.010 653.470 4.280 ;
        RECT 654.310 0.010 656.690 4.280 ;
        RECT 657.530 0.010 659.910 4.280 ;
        RECT 660.750 0.010 1187.990 4.280 ;
        RECT 1188.830 0.010 1191.210 4.280 ;
        RECT 1192.050 0.010 1194.430 4.280 ;
        RECT 1195.270 0.010 1197.650 4.280 ;
        RECT 1198.490 0.010 1200.870 4.280 ;
        RECT 1201.710 0.010 1220.190 4.280 ;
        RECT 1221.030 0.010 1223.410 4.280 ;
        RECT 1224.250 0.010 1233.070 4.280 ;
        RECT 1233.910 0.010 1242.730 4.280 ;
        RECT 1243.570 0.010 1245.950 4.280 ;
        RECT 1246.790 0.010 1274.930 4.280 ;
        RECT 1275.770 0.010 1278.150 4.280 ;
        RECT 1278.990 0.010 1281.370 4.280 ;
        RECT 1282.210 0.010 1287.810 4.280 ;
        RECT 1288.650 0.010 1291.030 4.280 ;
        RECT 1291.870 0.010 1294.250 4.280 ;
        RECT 1295.090 0.010 1297.470 4.280 ;
        RECT 1298.310 0.010 1300.690 4.280 ;
        RECT 1301.530 0.010 1303.910 4.280 ;
        RECT 1304.750 0.010 1307.130 4.280 ;
        RECT 1307.970 0.010 1310.350 4.280 ;
        RECT 1311.190 0.010 1313.570 4.280 ;
        RECT 1314.410 0.010 1316.790 4.280 ;
        RECT 1317.630 0.010 1320.010 4.280 ;
        RECT 1320.850 0.010 1323.230 4.280 ;
        RECT 1324.070 0.010 1326.450 4.280 ;
        RECT 1327.290 0.010 1329.670 4.280 ;
        RECT 1330.510 0.010 1332.890 4.280 ;
        RECT 1333.730 0.010 1336.110 4.280 ;
        RECT 1336.950 0.010 1339.330 4.280 ;
        RECT 1340.170 0.010 1342.550 4.280 ;
        RECT 1343.390 0.010 1345.770 4.280 ;
        RECT 1346.610 0.010 1348.990 4.280 ;
        RECT 1349.830 0.010 1352.210 4.280 ;
        RECT 1353.050 0.010 1355.430 4.280 ;
        RECT 1356.270 0.010 1358.650 4.280 ;
        RECT 1359.490 0.010 1361.870 4.280 ;
        RECT 1362.710 0.010 1365.090 4.280 ;
        RECT 1365.930 0.010 1368.310 4.280 ;
        RECT 1369.150 0.010 1371.530 4.280 ;
        RECT 1372.370 0.010 1374.750 4.280 ;
        RECT 1375.590 0.010 1377.970 4.280 ;
        RECT 1378.810 0.010 1381.190 4.280 ;
        RECT 1382.030 0.010 1384.410 4.280 ;
        RECT 1385.250 0.010 1387.630 4.280 ;
        RECT 1388.470 0.010 1390.850 4.280 ;
        RECT 1391.690 0.010 1394.070 4.280 ;
        RECT 1394.910 0.010 1397.290 4.280 ;
        RECT 1398.130 0.010 1400.510 4.280 ;
        RECT 1401.350 0.010 1403.730 4.280 ;
        RECT 1404.570 0.010 1406.950 4.280 ;
        RECT 1407.790 0.010 1410.170 4.280 ;
        RECT 1411.010 0.010 1413.390 4.280 ;
        RECT 1414.230 0.010 1416.610 4.280 ;
        RECT 1417.450 0.010 1419.830 4.280 ;
        RECT 1420.670 0.010 1423.050 4.280 ;
        RECT 1423.890 0.010 1426.270 4.280 ;
        RECT 1427.110 0.010 1429.490 4.280 ;
        RECT 1430.330 0.010 1503.550 4.280 ;
        RECT 1504.390 0.010 1506.770 4.280 ;
        RECT 1507.610 0.010 1509.990 4.280 ;
        RECT 1510.830 0.010 1542.190 4.280 ;
        RECT 1543.030 0.010 1545.410 4.280 ;
        RECT 1546.250 0.010 1548.630 4.280 ;
        RECT 1549.470 0.010 1860.970 4.280 ;
        RECT 1861.810 0.010 1864.190 4.280 ;
        RECT 1865.030 0.010 1893.170 4.280 ;
        RECT 1894.010 0.010 1909.270 4.280 ;
        RECT 1910.110 0.010 1928.590 4.280 ;
        RECT 1929.430 0.010 1931.810 4.280 ;
        RECT 1932.650 0.010 1957.570 4.280 ;
        RECT 1958.410 0.010 1983.330 4.280 ;
        RECT 1984.170 0.010 1986.550 4.280 ;
        RECT 1987.390 0.010 1992.990 4.280 ;
        RECT 1993.830 0.010 1996.210 4.280 ;
        RECT 1997.050 0.010 1999.430 4.280 ;
        RECT 2000.270 0.010 2002.650 4.280 ;
        RECT 2003.490 0.010 2012.310 4.280 ;
        RECT 2013.150 0.010 2050.950 4.280 ;
        RECT 2051.790 0.010 2076.710 4.280 ;
        RECT 2077.550 0.010 2096.030 4.280 ;
        RECT 2096.870 0.010 2099.250 4.280 ;
        RECT 2100.090 0.010 2118.570 4.280 ;
        RECT 2119.410 0.010 2121.790 4.280 ;
        RECT 2122.630 0.010 2125.010 4.280 ;
        RECT 2125.850 0.010 3588.370 4.280 ;
      LAYER met3 ;
        RECT 4.000 1779.240 3596.000 1787.545 ;
        RECT 4.000 1777.840 3595.600 1779.240 ;
        RECT 4.000 1775.840 3596.000 1777.840 ;
        RECT 4.000 1774.440 3595.600 1775.840 ;
        RECT 4.000 1772.440 3596.000 1774.440 ;
        RECT 4.000 1771.040 3595.600 1772.440 ;
        RECT 4.000 1769.040 3596.000 1771.040 ;
        RECT 4.000 1767.640 3595.600 1769.040 ;
        RECT 4.000 1765.640 3596.000 1767.640 ;
        RECT 4.000 1764.240 3595.600 1765.640 ;
        RECT 4.000 1762.240 3596.000 1764.240 ;
        RECT 4.000 1760.840 3595.600 1762.240 ;
        RECT 4.000 1758.840 3596.000 1760.840 ;
        RECT 4.000 1757.440 3595.600 1758.840 ;
        RECT 4.000 1755.440 3596.000 1757.440 ;
        RECT 4.000 1754.040 3595.600 1755.440 ;
        RECT 4.000 1707.840 3596.000 1754.040 ;
        RECT 4.000 1706.440 3595.600 1707.840 ;
        RECT 4.000 1687.440 3596.000 1706.440 ;
        RECT 4.000 1686.040 3595.600 1687.440 ;
        RECT 4.000 1680.640 3596.000 1686.040 ;
        RECT 4.000 1679.240 3595.600 1680.640 ;
        RECT 4.000 1673.840 3596.000 1679.240 ;
        RECT 4.000 1672.440 3595.600 1673.840 ;
        RECT 4.000 1595.640 3596.000 1672.440 ;
        RECT 4.000 1594.240 3595.600 1595.640 ;
        RECT 4.000 1571.840 3596.000 1594.240 ;
        RECT 4.000 1570.440 3595.600 1571.840 ;
        RECT 4.000 1517.440 3596.000 1570.440 ;
        RECT 4.000 1516.040 3595.600 1517.440 ;
        RECT 4.000 1432.440 3596.000 1516.040 ;
        RECT 4.000 1431.040 3595.600 1432.440 ;
        RECT 4.000 1405.240 3596.000 1431.040 ;
        RECT 4.000 1403.840 3595.600 1405.240 ;
        RECT 4.000 1361.040 3596.000 1403.840 ;
        RECT 4.000 1359.640 3595.600 1361.040 ;
        RECT 4.000 1259.040 3596.000 1359.640 ;
        RECT 4.000 1257.640 3595.600 1259.040 ;
        RECT 4.000 1208.040 3596.000 1257.640 ;
        RECT 4.000 1206.640 3595.600 1208.040 ;
        RECT 4.000 650.440 3596.000 1206.640 ;
        RECT 4.400 649.040 3596.000 650.440 ;
        RECT 4.000 0.175 3596.000 649.040 ;
      LAYER met4 ;
        RECT 82.175 926.880 138.290 1776.665 ;
        RECT 142.190 926.880 143.090 1776.665 ;
        RECT 146.990 927.800 238.290 1776.665 ;
        RECT 242.190 927.800 243.090 1776.665 ;
        RECT 146.990 926.880 243.090 927.800 ;
        RECT 246.990 927.800 338.290 1776.665 ;
        RECT 342.190 927.800 343.090 1776.665 ;
        RECT 246.990 926.880 343.090 927.800 ;
        RECT 346.990 926.880 438.290 1776.665 ;
        RECT 442.190 926.880 443.090 1776.665 ;
        RECT 446.990 926.880 538.290 1776.665 ;
        RECT 542.190 926.880 543.090 1776.665 ;
        RECT 546.990 926.880 638.290 1776.665 ;
        RECT 82.175 510.620 638.290 926.880 ;
        RECT 82.175 426.880 138.290 510.620 ;
        RECT 142.190 426.880 143.090 510.620 ;
        RECT 146.990 509.700 438.290 510.620 ;
        RECT 146.990 427.800 238.290 509.700 ;
        RECT 242.190 427.800 243.090 509.700 ;
        RECT 146.990 426.880 243.090 427.800 ;
        RECT 246.990 427.800 338.290 509.700 ;
        RECT 342.190 427.800 343.090 509.700 ;
        RECT 246.990 426.880 343.090 427.800 ;
        RECT 346.990 426.880 438.290 509.700 ;
        RECT 442.190 426.880 443.090 510.620 ;
        RECT 446.990 426.880 538.290 510.620 ;
        RECT 542.190 426.880 543.090 510.620 ;
        RECT 546.990 426.880 638.290 510.620 ;
        RECT 82.175 21.120 638.290 426.880 ;
        RECT 642.190 21.120 643.090 1776.665 ;
        RECT 646.990 926.880 738.290 1776.665 ;
        RECT 742.190 926.880 743.090 1776.665 ;
        RECT 746.990 927.800 838.290 1776.665 ;
        RECT 842.190 927.800 843.090 1776.665 ;
        RECT 846.990 927.800 938.290 1776.665 ;
        RECT 942.190 927.800 943.090 1776.665 ;
        RECT 946.990 927.800 1038.290 1776.665 ;
        RECT 746.990 926.880 1038.290 927.800 ;
        RECT 1042.190 926.880 1043.090 1776.665 ;
        RECT 1046.990 926.880 1138.290 1776.665 ;
        RECT 1142.190 926.880 1143.090 1776.665 ;
        RECT 1146.990 926.880 1238.290 1776.665 ;
        RECT 646.990 510.620 1238.290 926.880 ;
        RECT 646.990 426.880 738.290 510.620 ;
        RECT 742.190 426.880 743.090 510.620 ;
        RECT 746.990 509.700 1038.290 510.620 ;
        RECT 746.990 427.800 838.290 509.700 ;
        RECT 842.190 427.800 843.090 509.700 ;
        RECT 846.990 427.800 938.290 509.700 ;
        RECT 942.190 427.800 943.090 509.700 ;
        RECT 946.990 427.800 1038.290 509.700 ;
        RECT 746.990 426.880 1038.290 427.800 ;
        RECT 1042.190 426.880 1043.090 510.620 ;
        RECT 1046.990 426.880 1138.290 510.620 ;
        RECT 1142.190 426.880 1143.090 510.620 ;
        RECT 1146.990 426.880 1238.290 510.620 ;
        RECT 646.990 21.120 1238.290 426.880 ;
        RECT 1242.190 21.120 1243.090 1776.665 ;
        RECT 1246.990 21.120 1338.290 1776.665 ;
        RECT 1342.190 21.120 1343.090 1776.665 ;
        RECT 1346.990 926.880 1438.290 1776.665 ;
        RECT 1442.190 926.880 1443.090 1776.665 ;
        RECT 1446.990 927.800 1538.290 1776.665 ;
        RECT 1542.190 927.800 1543.090 1776.665 ;
        RECT 1546.990 927.800 1638.290 1776.665 ;
        RECT 1642.190 927.800 1643.090 1776.665 ;
        RECT 1646.990 927.800 1738.290 1776.665 ;
        RECT 1446.990 926.880 1738.290 927.800 ;
        RECT 1742.190 926.880 1743.090 1776.665 ;
        RECT 1746.990 926.880 1838.290 1776.665 ;
        RECT 1842.190 926.880 1843.090 1776.665 ;
        RECT 1846.990 926.880 1938.290 1776.665 ;
        RECT 1346.990 510.620 1938.290 926.880 ;
        RECT 1346.990 426.880 1438.290 510.620 ;
        RECT 1442.190 509.700 1738.290 510.620 ;
        RECT 1442.190 426.880 1443.090 509.700 ;
        RECT 1446.990 427.800 1538.290 509.700 ;
        RECT 1542.190 427.800 1543.090 509.700 ;
        RECT 1546.990 427.800 1638.290 509.700 ;
        RECT 1642.190 427.800 1643.090 509.700 ;
        RECT 1646.990 427.800 1738.290 509.700 ;
        RECT 1446.990 426.880 1738.290 427.800 ;
        RECT 1742.190 426.880 1743.090 510.620 ;
        RECT 1746.990 426.880 1838.290 510.620 ;
        RECT 1842.190 426.880 1843.090 510.620 ;
        RECT 1846.990 426.880 1938.290 510.620 ;
        RECT 1346.990 21.120 1938.290 426.880 ;
        RECT 1942.190 21.120 1943.090 1776.665 ;
        RECT 1946.990 926.880 2038.290 1776.665 ;
        RECT 2042.190 926.880 2043.090 1776.665 ;
        RECT 2046.990 926.880 2138.290 1776.665 ;
        RECT 2142.190 926.880 2143.090 1776.665 ;
        RECT 2146.990 926.880 2238.290 1776.665 ;
        RECT 2242.190 927.800 2243.090 1776.665 ;
        RECT 2246.990 927.800 2338.290 1776.665 ;
        RECT 2242.190 926.880 2338.290 927.800 ;
        RECT 2342.190 927.800 2343.090 1776.665 ;
        RECT 2346.990 927.800 2438.290 1776.665 ;
        RECT 2342.190 926.880 2438.290 927.800 ;
        RECT 2442.190 926.880 2443.090 1776.665 ;
        RECT 2446.990 926.880 2538.290 1776.665 ;
        RECT 1946.990 510.620 2538.290 926.880 ;
        RECT 1946.990 426.880 2038.290 510.620 ;
        RECT 2042.190 426.880 2043.090 510.620 ;
        RECT 2046.990 509.700 2343.090 510.620 ;
        RECT 2046.990 426.880 2138.290 509.700 ;
        RECT 2142.190 426.880 2143.090 509.700 ;
        RECT 2146.990 426.880 2238.290 509.700 ;
        RECT 2242.190 427.800 2243.090 509.700 ;
        RECT 2246.990 427.800 2338.290 509.700 ;
        RECT 2242.190 426.880 2338.290 427.800 ;
        RECT 2342.190 427.800 2343.090 509.700 ;
        RECT 2346.990 427.800 2438.290 510.620 ;
        RECT 2342.190 426.880 2438.290 427.800 ;
        RECT 2442.190 426.880 2443.090 510.620 ;
        RECT 2446.990 426.880 2538.290 510.620 ;
        RECT 1946.990 21.120 2538.290 426.880 ;
        RECT 2542.190 21.120 2543.090 1776.665 ;
        RECT 2546.990 21.120 2638.290 1776.665 ;
        RECT 2642.190 21.120 2643.090 1776.665 ;
        RECT 2646.990 926.880 2738.290 1776.665 ;
        RECT 2742.190 926.880 2743.090 1776.665 ;
        RECT 2746.990 926.880 2838.290 1776.665 ;
        RECT 2842.190 926.880 2843.090 1776.665 ;
        RECT 2846.990 927.800 2938.290 1776.665 ;
        RECT 2942.190 927.800 2943.090 1776.665 ;
        RECT 2946.990 927.800 3038.290 1776.665 ;
        RECT 3042.190 927.800 3043.090 1776.665 ;
        RECT 3046.990 927.800 3138.290 1776.665 ;
        RECT 2846.990 926.880 3138.290 927.800 ;
        RECT 3142.190 926.880 3143.090 1776.665 ;
        RECT 3146.990 926.880 3197.540 1776.665 ;
        RECT 2646.990 510.620 3197.540 926.880 ;
        RECT 2646.990 426.880 2738.290 510.620 ;
        RECT 2742.190 426.880 2743.090 510.620 ;
        RECT 2746.990 426.880 2838.290 510.620 ;
        RECT 2842.190 509.700 3138.290 510.620 ;
        RECT 2842.190 426.880 2843.090 509.700 ;
        RECT 2846.990 427.800 2938.290 509.700 ;
        RECT 2942.190 427.800 2943.090 509.700 ;
        RECT 2946.990 427.800 3038.290 509.700 ;
        RECT 3042.190 427.800 3043.090 509.700 ;
        RECT 3046.990 427.800 3138.290 509.700 ;
        RECT 2846.990 426.880 3138.290 427.800 ;
        RECT 3142.190 426.880 3143.090 510.620 ;
        RECT 3146.990 426.880 3197.540 510.620 ;
        RECT 2646.990 21.120 3197.540 426.880 ;
        RECT 82.175 0.175 3197.540 21.120 ;
  END
END rv32i_cpu_top
END LIBRARY

